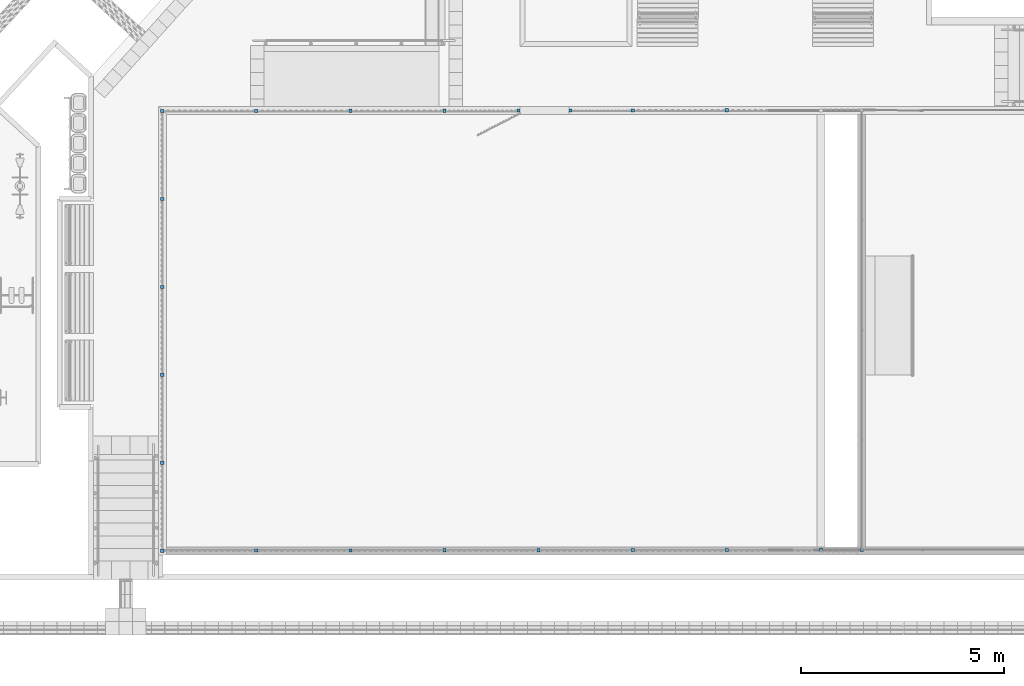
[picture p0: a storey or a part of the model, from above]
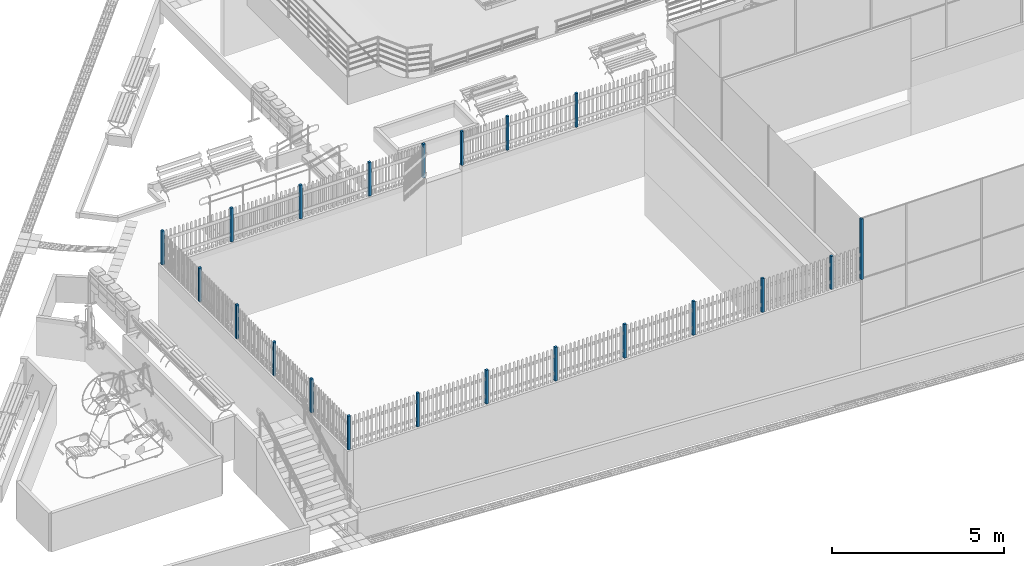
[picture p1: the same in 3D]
Properties of the parts of a building model (IFC2X3), part 1 of 2

# File
Description: ViewDefinition [CoordinationView_V2.0, QuantityTakeOffAddOnView], Option [Elements to export: Visible elements (on all stories)], Option [Partial Structure Display: Entire Model], Option [IFC Domain: All], Option [Structural Function: All Elements], Option [Convert Grid elements: On], Option [Convert IFC Annotations and ARCHICAD 2D elements: Off], Option [Convert 2D symbols of Doors and Windows: Off], Option [Export geometries that Participates in Collision Detection only: Off], Option [Split complex elements: Off], Option [Material Preservation: Explode where necessary], Option [Elements in Solid Element Operations: Extruded/revolved], Option [Elements with junctions: Extruded/revolved without junctions], Option [IFC Site Location: At Project Origin], Option [Curtain Wall export mode: Container Element], Option [Railing export mode: Single Element], Option [Stair export mode: Container Element], Option [Properties To Export: All properties], Option [Space containment: Off], Option [Bounding Box: Off], Option [Geometry to type objects: Off], Option [Element Properties: Visible Only], Option [Building Material Properties: Off], Option [Element Parameters: Off], Option [Component Parameters: All], Option [IFC Base Quantities: On], Option [Door Window Parameters: On], Option [IFC Space boundaries: Off], Option [ARCHICAD Zone Categories as IFC Space classification data: Off], Option [Element Classifications: On]
File name: C:\Users\Cleber\Desktop\Obra PRAÇA VILA SÃO JORGE. 22 SETEMBRO.ifc
Time: 2023-09-26T13:36:35
Author: Architect
Organization: Building Designer Office
Written by: The EXPRESS Data Manager Version 5.02.0100.09 : 26 Sep 2013
Made in: IFC file generated by GRAPHISOFT ARCHICAD 25.0.0 BRA FULL Windows version (IFC add-on version: 3002 BRA FULL).
Authorization: The authorising person

# IfcSite, Local
RefLatitude: -23, -32, 0, 0; RefLongitude: -46, -38, 0, 0; RefElevation: 0 mm
BaseQuantities - GrossPerimeter: 0 mm; GrossArea: 0 m2

# IfcBuilding, Construção
BaseQuantities - GrossFloorArea: 0 m2

# IfcBuildingStorey, Pavimento Térreo
In: Construção
Elevation: 0 mm
BaseQuantities - NetHeight: 3000 mm; GrossHeight: 3000 mm; Height: 3000 mm; GrossFloorArea: 0 m2

# IfcBeam: GENÉRICO - ESTRUTURAL 120 x 1000 (2)
In: Pavimento Térreo
Classification: Viga (Classificação ARCHICAD); Material: GENÉRICO - ESTRUTURAL
AC_Pset_RenovationAndPhasing - Renovation Status: Existing
Pset_BeamCommon - Reference: GENÉRICO - ESTRUTURAL 120 x 1000
Component Properties - Component 1, Tipo de Componente: Núcleo
BaseQuantities - Width: 120 mm; Depth: 999.792 mm; CrossSectionArea: 0.119975 m2
Component Quantities - Component 1, Espessura do Componente: 120 mm; Component 1, Altura do Componente Retangular: 999.792 mm; Component 1, Largura do Componente Retangular: 120 mm; Component 1, Área de Seção Transversal do Componente: 0.119975 m2
Name | Component 1, Carbono Incorporado | Component 1, Energia Incorporada (MJ) | NetSurfaceAreaExtrudedSides (m2) = OuterSurfaceArea (m2) | Length (mm) | TotalSurfaceArea (m2) = GrossSurfaceArea (m2) = NetSurfaceArea (m2) | GrossVolume (m3) | NetVolume (m3) = Component 1, Volume Componente (Líquido) (m3) = Component 1, Volume do componente (Bruto) (m3) | Component 1, Massa (kg) | Component 1, Área de Componente Projetada (Líquida) (m2) = Component 1, Área de Componente Projetada (Bruta) (m2)
Viga-032 | 41.9005 (kgCO₂) | 406.308 | 1.69798 | 1462.07 | 1.93793 | 0.174822 | 0.0920082 | 211.619 | 0.784363
Viga-032 | 79.3958 (kgCO₂) | 769.898 | 3.24369 | 1493.59 | 3.48364 | 0.177655 | 0.174343 | 400.989 | 1.4932

# IfcBeam: GENÉRICO - ESTRUTURAL 120 x 1362 (8)
In: Pavimento Térreo
Classification: Viga (Classificação ARCHICAD); Material: GENÉRICO - ESTRUTURAL
AC_Pset_RenovationAndPhasing - Renovation Status: Existing
Pset_BeamCommon - Reference: GENÉRICO - ESTRUTURAL 120 x 1362
Component Properties - Component 1, Tipo de Componente: Núcleo
BaseQuantities - Width: 120 mm; Depth: 1361.64 mm; CrossSectionArea: 0.163396 m2
Component Quantities - Component 1, Espessura do Componente: 120 mm; Component 1, Altura do Componente Retangular: 1361.64 mm; Component 1, Largura do Componente Retangular: 120 mm; Component 1, Área de Seção Transversal do Componente: 0.163396 m2
Name | Component 1, Carbono Incorporado | Component 1, Energia Incorporada (MJ) | NetSurfaceAreaExtrudedSides (m2) = OuterSurfaceArea (m2) | Length (mm) | TotalSurfaceArea (m2) = GrossSurfaceArea (m2) = NetSurfaceArea (m2) | GrossVolume (m3) | NetVolume (m3) = Component 1, Volume Componente (Líquido) (m3) = Component 1, Volume do componente (Bruto) (m3) | Component 1, Massa (kg) | Component 1, Área de Componente Projetada (Líquida) (m2) = Component 1, Área de Componente Projetada (Bruta) (m2)
Viga-031 | 380.983 (kgCO₂) | 3694.38 | 15.172 | 5240 | 15.4987 | 0.836589 | 0.836589 | 1924.16 | 7.10132
Viga-031 | 581.999 (kgCO₂) | 5643.63 | 23.1771 | 7907.69 | 23.5039 | 1.278 | 1.278 | 2939.39 | 10.7674
Viga-031 | 110.547 (kgCO₂) | 1071.97 | 4.40235 | 1511.88 | 4.72914 | 0.242748 | 0.242748 | 558.32 | 2.05863
Viga-031 | 118.178 (kgCO₂) | 1145.97 | 4.7643 | 1656.84 | 5.09109 | 0.266916 | 0.259503 | 596.857 | 2.25602
Viga-032 | 369.15 (kgCO₂) | 3579.64 | 14.7007 | 5007.56 | 15.0275 | 0.810606 | 0.810606 | 1864.39 | 6.81848
Viga-031 | 426.373 (kgCO₂) | 4134.53 | 16.9796 | 5850 | 17.3063 | 0.936261 | 0.936261 | 2153.4 | 7.96557
Viga-031 | 16.4181 (kgCO₂) | 159.206 | 0.653821 | 220.642 | 0.980614 | 0.036052 | 0.036052 | 82.9197 | 0.300434
Viga-031 | 138.486 (kgCO₂) | 1342.9 | 5.51497 | 1944.4 | 5.84176 | 0.304098 | 0.304098 | 699.426 | 2.64757

# IfcBeam: GENÉRICO - ESTRUTURAL 120 x 1535, Viga-030
In: Pavimento Térreo
Classification: Viga (Classificação ARCHICAD); Material: GENÉRICO - ESTRUTURAL
AC_Pset_RenovationAndPhasing - Renovation Status: Existing
Pset_BeamCommon - Reference: GENÉRICO - ESTRUTURAL 120 x 1535
Component Properties - Component 1, Carbono Incorporado: 63.7385 (kgCO₂); Component 1, Energia Incorporada: 618.07 MJ; Component 1, Tipo de Componente: Núcleo
BaseQuantities - NetSurfaceAreaExtrudedSides: 2.51505 m2; Length: 911.723 mm; Width: 120 mm; Depth: 1535.02 mm; CrossSectionArea: 0.184202 m2; OuterSurfaceArea: 2.51505 m2; TotalSurfaceArea: 2.88345 m2; GrossSurfaceArea: 2.88345 m2; GrossVolume: 0.139961 m3; NetSurfaceArea: 2.88345 m2; NetVolume: 0.139961 m3
Component Quantities - Component 1, Massa: 321.911 kg; Component 1, Área de Componente Projetada (Líquida): 1.368 m2; Component 1, Área de Componente Projetada (Bruta): 1.368 m2; Component 1, Espessura do Componente: 120 mm; Component 1, Altura do Componente Retangular: 1535.02 mm; Component 1, Largura do Componente Retangular: 120 mm; Component 1, Área de Seção Transversal do Componente: 0.184202 m2; Component 1, Volume Componente (Líquido): 0.139961 m3; Component 1, Volume do componente (Bruto): 0.139961 m3

# IfcBeam: GENÉRICO - ESTRUTURAL 120 x 2013, Viga-030
In: Pavimento Térreo
Classification: Viga (Classificação ARCHICAD); Material: GENÉRICO - ESTRUTURAL
AC_Pset_RenovationAndPhasing - Renovation Status: Existing
Pset_BeamCommon - Reference: GENÉRICO - ESTRUTURAL 120 x 2013
Component Properties - Component 1, Carbono Incorporado: 146.516 (kgCO₂); Component 1, Energia Incorporada: 1420.76 MJ; Component 1, Tipo de Componente: Núcleo
BaseQuantities - NetSurfaceAreaExtrudedSides: 5.68184 m2; Length: 1440.63 mm; Width: 120 mm; Depth: 2012.87 mm; CrossSectionArea: 0.241545 m2; OuterSurfaceArea: 5.68184 m2; TotalSurfaceArea: 6.16493 m2; GrossSurfaceArea: 6.16493 m2; GrossVolume: 0.32173 m3; NetSurfaceArea: 6.16493 m2; NetVolume: 0.32173 m3
Component Quantities - Component 1, Massa: 739.979 kg; Component 1, Área de Componente Projetada (Líquida): 2.80498 m2; Component 1, Área de Componente Projetada (Bruta): 2.80498 m2; Component 1, Espessura do Componente: 120 mm; Component 1, Altura do Componente Retangular: 2012.87 mm; Component 1, Largura do Componente Retangular: 120 mm; Component 1, Área de Seção Transversal do Componente: 0.241545 m2; Component 1, Volume Componente (Líquido): 0.32173 m3; Component 1, Volume do componente (Bruto): 0.32173 m3

# IfcBeam: GENÉRICO - ESTRUTURAL 120 x 340, Viga-032
In: Pavimento Térreo
Classification: Viga (Classificação ARCHICAD); Material: GENÉRICO - ESTRUTURAL
AC_Pset_RenovationAndPhasing - Renovation Status: Existing
Pset_BeamCommon - Reference: GENÉRICO - ESTRUTURAL 120 x 340
Component Properties - Component 1, Carbono Incorporado: 412.235 (kgCO₂); Component 1, Energia Incorporada: 3997.43 MJ; Component 1, Tipo de Componente: Núcleo
BaseQuantities - NetSurfaceAreaExtrudedSides: 20.4091 m2; Length: 22225.5 mm; Width: 120 mm; Depth: 340.166 mm; CrossSectionArea: 0.04082 m2; OuterSurfaceArea: 20.4091 m2; TotalSurfaceArea: 20.4908 m2; GrossSurfaceArea: 20.4908 m2; GrossVolume: 0.906422 m3; NetSurfaceArea: 20.4908 m2; NetVolume: 0.905215 m3
Component Quantities - Component 1, Massa: 2081.99 kg; Component 1, Área de Componente Projetada (Líquida): 7.56037 m2; Component 1, Área de Componente Projetada (Bruta): 7.56037 m2; Component 1, Espessura do Componente: 120 mm; Component 1, Altura do Componente Retangular: 340.166 mm; Component 1, Largura do Componente Retangular: 120 mm; Component 1, Área de Seção Transversal do Componente: 0.04082 m2; Component 1, Volume Componente (Líquido): 0.905215 m3; Component 1, Volume do componente (Bruto): 0.905215 m3

# IfcBeam: GENÉRICO - ESTRUTURAL 120 x 500 (2)
In: Pavimento Térreo
Classification: Viga (Classificação ARCHICAD); Material: GENÉRICO - ESTRUTURAL
AC_Pset_RenovationAndPhasing - Renovation Status: Existing
Pset_BeamCommon - Reference: GENÉRICO - ESTRUTURAL 120 x 500
Component Properties - Component 1, Tipo de Componente: Núcleo
BaseQuantities - Width: 120 mm; Depth: 499.897 mm; CrossSectionArea: 0.0599877 m2
Component Quantities - Component 1, Espessura do Componente: 120 mm; Component 1, Altura do Componente Retangular: 499.897 mm; Component 1, Largura do Componente Retangular: 120 mm; Component 1, Área de Seção Transversal do Componente: 0.0599877 m2
Name | Component 1, Carbono Incorporado | Component 1, Energia Incorporada (MJ) | NetSurfaceAreaExtrudedSides (m2) = OuterSurfaceArea (m2) | Length (mm) | TotalSurfaceArea (m2) = GrossSurfaceArea (m2) = NetSurfaceArea (m2) | GrossVolume (m3) | NetVolume (m3) = Component 1, Volume Componente (Líquido) (m3) = Component 1, Volume do componente (Bruto) (m3) | Component 1, Massa (kg) | Component 1, Área de Componente Projetada (Líquida) (m2) = Component 1, Área de Componente Projetada (Bruta) (m2)
Viga-032 | 193.354 (kgCO₂) | 1874.95 | 12.4029 | 22225.8 | 12.5229 | 1.33029 | 0.424581 | 976.537 | 3.54959
Viga-032 | 40.92 (kgCO₂) | 396.8 | 1.85708 | 1586.63 | 1.97706 | 0.089856 | 0.0898551 | 206.667 | 0.78175

# IfcBeam: GENÉRICO - ESTRUTURAL 120 x 580, Viga-030
In: Pavimento Térreo
Classification: Viga (Classificação ARCHICAD); Material: GENÉRICO - ESTRUTURAL
AC_Pset_RenovationAndPhasing - Renovation Status: Existing
Pset_BeamCommon - Reference: GENÉRICO - ESTRUTURAL 120 x 580
Component Properties - Component 1, Carbono Incorporado: 157.502 (kgCO₂); Component 1, Energia Incorporada: 1527.3 MJ; Component 1, Tipo de Componente: Núcleo
BaseQuantities - NetSurfaceAreaExtrudedSides: 6.92989 m2; Length: 4976.72 mm; Width: 120 mm; Depth: 579.51 mm; CrossSectionArea: 0.0695413 m2; OuterSurfaceArea: 6.92989 m2; TotalSurfaceArea: 7.06897 m2; GrossSurfaceArea: 7.06897 m2; GrossVolume: 0.345858 m3; NetSurfaceArea: 7.06897 m2; NetVolume: 0.345855 m3
Component Quantities - Component 1, Massa: 795.467 kg; Component 1, Área de Componente Projetada (Líquida): 2.88215 m2; Component 1, Área de Componente Projetada (Bruta): 2.88215 m2; Component 1, Espessura do Componente: 120 mm; Component 1, Altura do Componente Retangular: 579.51 mm; Component 1, Largura do Componente Retangular: 120 mm; Component 1, Área de Seção Transversal do Componente: 0.0695413 m2; Component 1, Volume Componente (Líquido): 0.345855 m3; Component 1, Volume do componente (Bruto): 0.345855 m3

# IfcBeam: GENÉRICO - ESTRUTURAL 120 x 585 (3)
In: Pavimento Térreo
Classification: Viga (Classificação ARCHICAD); Material: GENÉRICO - ESTRUTURAL
AC_Pset_RenovationAndPhasing - Renovation Status: Existing
Pset_BeamCommon - Reference: GENÉRICO - ESTRUTURAL 120 x 585
Component Properties - Component 1, Tipo de Componente: Núcleo
BaseQuantities - Width: 120 mm; Depth: 584.595 mm; CrossSectionArea: 0.0701514 m2
Component Quantities - Component 1, Espessura do Componente: 120 mm; Component 1, Altura do Componente Retangular: 584.595 mm; Component 1, Largura do Componente Retangular: 120 mm; Component 1, Área de Seção Transversal do Componente: 0.0701514 m2
Name | Component 1, Carbono Incorporado | Component 1, Energia Incorporada (MJ) | NetSurfaceAreaExtrudedSides (m2) = OuterSurfaceArea (m2) | Length (mm) | TotalSurfaceArea (m2) = GrossSurfaceArea (m2) = NetSurfaceArea (m2) | GrossVolume (m3) | NetVolume (m3) = Component 1, Volume Componente (Líquido) (m3) = Component 1, Volume do componente (Bruto) (m3) | Component 1, Massa (kg) | Component 1, Área de Componente Projetada (Líquida) (m2) = Component 1, Área de Componente Projetada (Bruta) (m2)
Viga-031 | 326.185 (kgCO₂) | 3163.01 | 14.388 | 10254.9 | 14.5283 | 0.716272 | 0.716261 | 1647.4 | 5.96893
Viga-031 | 37.8124 (kgCO₂) | 366.666 | 1.67025 | 1231.48 | 1.81055 | 0.0832676 | 0.0830312 | 190.972 | 0.693897
Viga-031 | 41.8068 (kgCO₂) | 405.399 | 1.84411 | 1322.81 | 1.98441 | 0.0918023 | 0.0918023 | 211.145 | 0.765019

# IfcBeam: GENÉRICO - ESTRUTURAL 120 x 725, Viga-032
In: Pavimento Térreo
Classification: Viga (Classificação ARCHICAD); Material: GENÉRICO - ESTRUTURAL
AC_Pset_RenovationAndPhasing - Renovation Status: Existing
Pset_BeamCommon - Reference: GENÉRICO - ESTRUTURAL 120 x 725
Component Properties - Component 1, Carbono Incorporado: 5.61509 (kgCO₂); Component 1, Energia Incorporada: 54.4493 MJ; Component 1, Tipo de Componente: Núcleo
BaseQuantities - NetSurfaceAreaExtrudedSides: 0.382527 m2; Length: 1494.2 mm; Width: 120 mm; Depth: 724.825 mm; CrossSectionArea: 0.086979 m2; OuterSurfaceArea: 0.382527 m2; TotalSurfaceArea: 0.556485 m2; GrossSurfaceArea: 0.556485 m2; GrossVolume: 0.125256 m3; NetSurfaceArea: 0.556485 m2; NetVolume: 0.01233 m3
Component Quantities - Component 1, Massa: 28.359 kg; Component 1, Área de Componente Projetada (Líquida): 0.111382 m2; Component 1, Área de Componente Projetada (Bruta): 0.111382 m2; Component 1, Espessura do Componente: 120 mm; Component 1, Altura do Componente Retangular: 724.825 mm; Component 1, Largura do Componente Retangular: 120 mm; Component 1, Área de Seção Transversal do Componente: 0.086979 m2; Component 1, Volume Componente (Líquido): 0.01233 m3; Component 1, Volume do componente (Bruto): 0.01233 m3

# IfcBeam: GENÉRICO - ESTRUTURAL 120 x 766, Viga-031
In: Pavimento Térreo
Classification: Viga (Classificação ARCHICAD); Material: GENÉRICO - ESTRUTURAL
AC_Pset_RenovationAndPhasing - Renovation Status: Existing
Pset_BeamCommon - Reference: GENÉRICO - ESTRUTURAL 120 x 766
Component Properties - Component 1, Carbono Incorporado: 50.8274 (kgCO₂); Component 1, Energia Incorporada: 492.872 MJ; Component 1, Tipo de Componente: Núcleo
BaseQuantities - NetSurfaceAreaExtrudedSides: 2.1515 m2; Length: 1295.36 mm; Width: 120 mm; Depth: 766.231 mm; CrossSectionArea: 0.0919477 m2; OuterSurfaceArea: 2.1515 m2; TotalSurfaceArea: 2.33539 m2; GrossSurfaceArea: 2.33539 m2; GrossVolume: 0.111611 m3; NetSurfaceArea: 2.33539 m2; NetVolume: 0.11161 m3
Component Quantities - Component 1, Massa: 256.704 kg; Component 1, Área de Componente Projetada (Líquida): 0.930088 m2; Component 1, Área de Componente Projetada (Bruta): 0.930088 m2; Component 1, Espessura do Componente: 120 mm; Component 1, Altura do Componente Retangular: 766.231 mm; Component 1, Largura do Componente Retangular: 120 mm; Component 1, Área de Seção Transversal do Componente: 0.0919477 m2; Component 1, Volume Componente (Líquido): 0.111611 m3; Component 1, Volume do componente (Bruto): 0.111611 m3

# IfcBeam: GENÉRICO - ESTRUTURAL 120 x 826, Viga-032
In: Pavimento Térreo
Classification: Viga (Classificação ARCHICAD); Material: GENÉRICO - ESTRUTURAL
AC_Pset_RenovationAndPhasing - Renovation Status: Existing
Pset_BeamCommon - Reference: GENÉRICO - ESTRUTURAL 120 x 826
Component Properties - Component 1, Carbono Incorporado: 34.3697 (kgCO₂); Component 1, Energia Incorporada: 333.282 MJ; Component 1, Tipo de Componente: Núcleo
BaseQuantities - NetSurfaceAreaExtrudedSides: 1.4405 m2; Length: 910.737 mm; Width: 120 mm; Depth: 826.435 mm; CrossSectionArea: 0.0991722 m2; OuterSurfaceArea: 1.4405 m2; TotalSurfaceArea: 1.63885 m2; GrossSurfaceArea: 1.63885 m2; GrossVolume: 0.0754715 m3; NetSurfaceArea: 1.63885 m2; NetVolume: 0.0754715 m3
Component Quantities - Component 1, Massa: 173.584 kg; Component 1, Área de Componente Projetada (Líquida): 0.752142 m2; Component 1, Área de Componente Projetada (Bruta): 0.752142 m2; Component 1, Espessura do Componente: 120 mm; Component 1, Altura do Componente Retangular: 826.435 mm; Component 1, Largura do Componente Retangular: 120 mm; Component 1, Área de Seção Transversal do Componente: 0.0991722 m2; Component 1, Volume Componente (Líquido): 0.0754715 m3; Component 1, Volume do componente (Bruto): 0.0754715 m3

# IfcBeam: GENÉRICO - ESTRUTURAL 120 x 835, Viga-033
In: Pavimento Térreo
Classification: Viga (Classificação ARCHICAD); Material: GENÉRICO - ESTRUTURAL
AC_Pset_RenovationAndPhasing - Renovation Status: Existing
Pset_BeamCommon - Reference: GENÉRICO - ESTRUTURAL 120 x 835
Component Properties - Component 1, Carbono Incorporado: 137.254 (kgCO₂); Component 1, Energia Incorporada: 1330.95 MJ; Component 1, Tipo de Componente: Núcleo
BaseQuantities - NetSurfaceAreaExtrudedSides: 5.74554 m2; Length: 3101.42 mm; Width: 120 mm; Depth: 834.502 mm; CrossSectionArea: 0.10014 m2; OuterSurfaceArea: 5.74554 m2; TotalSurfaceArea: 5.94582 m2; GrossSurfaceArea: 5.94582 m2; GrossVolume: 0.301393 m3; NetSurfaceArea: 5.94582 m2; NetVolume: 0.301393 m3
Component Quantities - Component 1, Massa: 693.203 kg; Component 1, Área de Componente Projetada (Líquida): 2.56793 m2; Component 1, Área de Componente Projetada (Bruta): 2.56793 m2; Component 1, Espessura do Componente: 120 mm; Component 1, Altura do Componente Retangular: 834.502 mm; Component 1, Largura do Componente Retangular: 120 mm; Component 1, Área de Seção Transversal do Componente: 0.10014 m2; Component 1, Volume Componente (Líquido): 0.301393 m3; Component 1, Volume do componente (Bruto): 0.301393 m3

# IfcBeam: GENÉRICO - ESTRUTURAL 120 x 919 (18)
In: Pavimento Térreo
Classification: Viga (Classificação ARCHICAD); Material: GENÉRICO - ESTRUTURAL
AC_Pset_RenovationAndPhasing - Renovation Status: Existing
Pset_BeamCommon - Reference: GENÉRICO - ESTRUTURAL 120 x 919
Component Properties - Component 1, Tipo de Componente: Núcleo
BaseQuantities - Width: 120 mm; Depth: 919.288 mm; CrossSectionArea: 0.110315 m2
Component Quantities - Component 1, Espessura do Componente: 120 mm; Component 1, Altura do Componente Retangular: 919.288 mm; Component 1, Largura do Componente Retangular: 120 mm; Component 1, Área de Seção Transversal do Componente: 0.110315 m2
Name | Component 1, Carbono Incorporado | Component 1, Energia Incorporada (MJ) | NetSurfaceAreaExtrudedSides (m2) = OuterSurfaceArea (m2) | Length (mm) | TotalSurfaceArea (m2) = GrossSurfaceArea (m2) = NetSurfaceArea (m2) | GrossVolume (m3) | NetVolume (m3) = Component 1, Volume Componente (Líquido) (m3) = Component 1, Volume do componente (Bruto) (m3) | Component 1, Massa (kg) | Component 1, Área de Componente Projetada (Líquida) (m2) = Component 1, Área de Componente Projetada (Bruta) (m2)
Viga-030 | 106.903 (kgCO₂) | 1036.63 | 4.42318 | 2164.82 | 4.64381 | 0.234748 | 0.234745 | 539.913 | 1.95624
Viga-030 | 24.6152 (kgCO₂) | 238.693 | 1.02325 | 544.505 | 1.24388 | 0.0595885 | 0.0540518 | 124.319 | 0.45064
Viga-030 | 37.6315 (kgCO₂) | 364.911 | 1.55701 | 756.572 | 1.77764 | 0.0826339 | 0.0826339 | 190.058 | 0.688616
Viga-031 | 1133.76 (kgCO₂) | 10994 | 46.9173 | 22648.5 | 47.1379 | 2.49982 | 2.48959 | 5726.06 | 20.7466
Viga-032 | 650.457 (kgCO₂) | 6307.46 | 26.9128 | 12972.3 | 27.1334 | 1.42832 | 1.42832 | 3285.14 | 11.9027
Viga-030 | 656.273 (kgCO₂) | 6363.86 | 27.1534 | 13314.7 | 27.3741 | 1.44109 | 1.44109 | 3314.51 | 12.1371
Viga-030 | 58.5463 (kgCO₂) | 567.722 | 2.42244 | 1270.82 | 2.64307 | 0.128564 | 0.12856 | 295.688 | 1.10597
Viga-031 | 414.104 (kgCO₂) | 4015.56 | 17.1333 | 8304.88 | 17.3539 | 0.909343 | 0.90932 | 2091.44 | 7.59058
Viga-031 | 2067.89 (kgCO₂) | 20052.3 | 85.5594 | 41211.6 | 85.78 | 4.54082 | 4.54082 | 10443.9 | 37.8402
Viga-031 | 38.621 (kgCO₂) | 374.507 | 1.59795 | 768.772 | 1.81858 | 0.0848067 | 0.0848067 | 195.055 | 0.706723
Viga-030 | 36.961 (kgCO₂) | 358.41 | 1.52927 | 760.809 | 1.7499 | 0.0811617 | 0.0811617 | 186.672 | 0.676348
Viga-030 | 4.45229 (kgCO₂) | 43.1737 | 0.190464 | 214.343 | 0.411093 | 0.0167333 | 0.00977666 | 22.4863 | 0.109912
Viga-030 | 158.607 (kgCO₂) | 1538.01 | 6.5624 | 3225.61 | 6.78303 | 0.348286 | 0.348282 | 801.047 | 2.92697
Viga-030 | 363.83 (kgCO₂) | 3528.05 | 15.0535 | 7481.73 | 15.2742 | 0.798924 | 0.798924 | 1837.52 | 6.77924
Viga-032 | 192.432 (kgCO₂) | 1866.01 | 10.9101 | 6921.34 | 11.1308 | 0.756157 | 0.422556 | 971.879 | 6.31226
Viga-032 | 236.974 (kgCO₂) | 2297.93 | 9.81061 | 4767.43 | 10.0312 | 0.520365 | 0.520365 | 1196.84 | 4.3393
Viga-031 | 1234.43 (kgCO₂) | 11970.2 | 51.0293 | 24643.2 | 51.25 | 2.71066 | 2.71065 | 6234.49 | 22.5889
Viga-030 | 67.0916 (kgCO₂) | 650.585 | 2.77589 | 1372.31 | 2.99652 | 0.160571 | 0.147325 | 338.847 | 1.22769

# IfcBeam: GENÉRICO - ESTRUTURAL 150 x 300 (3)
In: Pavimento Térreo
Classification: Viga (Classificação ARCHICAD); Material: GENÉRICO - ESTRUTURAL
AC_Pset_RenovationAndPhasing - Renovation Status: Existing
Pset_BeamCommon - Reference: GENÉRICO - ESTRUTURAL 150 x 300
Component Properties - Component 1, Tipo de Componente: Núcleo
BaseQuantities - Width: 150 mm; Depth: 300 mm; CrossSectionArea: 0.045 m2
Component Quantities - Component 1, Espessura do Componente: 150 mm; Component 1, Altura do Componente Retangular: 300 mm; Component 1, Largura do Componente Retangular: 150 mm; Component 1, Área de Seção Transversal do Componente: 0.045 m2
Name | Component 1, Carbono Incorporado | Component 1, Energia Incorporada (MJ) | NetSurfaceAreaExtrudedSides (m2) = OuterSurfaceArea (m2) | Length (mm) | TotalSurfaceArea (m2) = GrossSurfaceArea (m2) = NetSurfaceArea (m2) | GrossVolume (m3) = NetVolume (m3) = Component 1, Volume Componente (Líquido) (m3) = Component 1, Volume do componente (Bruto) (m3) | Component 1, Massa (kg) | Component 1, Área de Componente Projetada (Líquida) (m2) = Component 1, Área de Componente Projetada (Bruta) (m2)
Viga-032 | 30.7395 (kgCO₂) | 298.08 | 1.35 | 1500 | 1.44 | 0.0675 | 155.25 | 0.45
Viga-032 | 40.9602 (kgCO₂) | 397.19 | 1.79887 | 1998.74 | 1.88887 | 0.0899434 | 206.87 | 0.599623
Viga-032 | 88.2772 (kgCO₂) | 856.021 | 3.87691 | 4325.61 | 3.96691 | 0.193845 | 445.844 | 1.2923

# IfcBeam: GENÉRICO - ESTRUTURAL 200 x 1997, Viga-032
In: Pavimento Térreo
Classification: Viga (Classificação ARCHICAD); Material: GENÉRICO - ESTRUTURAL
AC_Pset_RenovationAndPhasing - Renovation Status: Existing
Pset_BeamCommon - Reference: GENÉRICO - ESTRUTURAL 200 x 1997
Component Properties - Component 1, Carbono Incorporado: 3058.17 (kgCO₂); Component 1, Energia Incorporada: 29655 MJ; Component 1, Tipo de Componente: Núcleo
BaseQuantities - NetSurfaceAreaExtrudedSides: 73.8784 m2; Length: 16929.8 mm; Width: 200 mm; Depth: 1997.15 mm; CrossSectionArea: 0.399429 m2; OuterSurfaceArea: 73.8784 m2; TotalSurfaceArea: 74.6773 m2; GrossSurfaceArea: 74.6773 m2; GrossVolume: 6.71536 m3; NetSurfaceArea: 74.6773 m2; NetVolume: 6.71535 m3
Component Quantities - Component 1, Massa: 15445.3 kg; Component 1, Área de Componente Projetada (Líquida): 33.5768 m2; Component 1, Área de Componente Projetada (Bruta): 33.5768 m2; Component 1, Espessura do Componente: 200 mm; Component 1, Altura do Componente Retangular: 1997.15 mm; Component 1, Largura do Componente Retangular: 200 mm; Component 1, Área de Seção Transversal do Componente: 0.399429 m2; Component 1, Volume Componente (Líquido): 6.71535 m3; Component 1, Volume do componente (Bruto): 6.71535 m3

# IfcBeam: GENÉRICO - ESTRUTURAL 400 x 20 (24)
In: Pavimento Térreo
Classification: Viga (Classificação ARCHICAD); Material: GENÉRICO - ESTRUTURAL
AC_Pset_RenovationAndPhasing - Renovation Status: Existing
Pset_BeamCommon - Reference: GENÉRICO - ESTRUTURAL 400 x 20
Component Properties - Component 1, Tipo de Componente: Núcleo
BaseQuantities - Width: 400 mm; Depth: 20 mm; CrossSectionArea: 0.008 m2
Component Quantities - Component 1, Espessura do Componente: 400 mm; Component 1, Altura do Componente Retangular: 20 mm; Component 1, Largura do Componente Retangular: 400 mm; Component 1, Área de Seção Transversal do Componente: 0.008 m2
Name | Component 1, Carbono Incorporado | Component 1, Energia Incorporada (MJ) | NetSurfaceAreaExtrudedSides (m2) = OuterSurfaceArea (m2) | Length (mm) | TotalSurfaceArea (m2) = GrossSurfaceArea (m2) = NetSurfaceArea (m2) | GrossVolume (m3) = NetVolume (m3) = Component 1, Volume Componente (Líquido) (m3) = Component 1, Volume do componente (Bruto) (m3) | Component 1, Massa (kg) | Component 1, Área de Componente Projetada (Líquida) (m2) = Component 1, Área de Componente Projetada (Bruta) (m2)
7 x Viga-031 | 14.5899 (kgCO₂) | 141.478 | 3.36394 | 4005.66 | 3.37994 | 0.0320375 | 73.6863 | 0.0800938
2 x Viga-031 | 14.6156 (kgCO₂) | 141.727 | 3.36988 | 4013.29 | 3.38588 | 0.0320941 | 73.8164 | 0.0802352
2 x Viga-031 | 14.6207 (kgCO₂) | 141.776 | 3.37104 | 4014.77 | 3.38704 | 0.0321052 | 73.8419 | 0.0802629
6 x Viga-031 | 14.6214 (kgCO₂) | 141.784 | 3.37121 | 4014.98 | 3.38721 | 0.0321068 | 73.8456 | 0.080267
2 x Viga-031 | 14.6188 (kgCO₂) | 141.758 | 3.37061 | 4014.22 | 3.38661 | 0.032101 | 73.8324 | 0.0802526
2 x Viga-031 | 14.6184 (kgCO₂) | 141.754 | 3.37051 | 4014.09 | 3.38651 | 0.0321001 | 73.8301 | 0.0802502
2 x Viga-031 | 14.6167 (kgCO₂) | 141.737 | 3.37011 | 4013.59 | 3.38611 | 0.0320963 | 73.8215 | 0.0802407
Viga-031 | 14.5896 (kgCO₂) | 141.475 | 3.36388 | 4005.59 | 3.37988 | 0.032037 | 73.6851 | 0.0800925

# IfcBeam: GENÉRICO - ESTRUTURAL D30 (18)
In: Pavimento Térreo
Classification: Viga (Classificação ARCHICAD); Material: GENÉRICO - ESTRUTURAL
AC_Pset_RenovationAndPhasing - Renovation Status: Existing
Pset_BeamCommon - Reference: GENÉRICO - ESTRUTURAL D30
Component Properties - Component 1, Tipo de Componente: Núcleo
BaseQuantities - Width: 30 mm; Depth: 30 mm; CrossSectionArea: 0.000706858 m2
Component Quantities - Component 1, Espessura do Componente: 30 mm; Component 1, Área de Seção Transversal do Componente: 0.000706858 m2
Name | Component 1, Carbono Incorporado | Component 1, Energia Incorporada (MJ) | NetSurfaceAreaExtrudedSides (m2) = OuterSurfaceArea (m2) | Length (mm) | TotalSurfaceArea (m2) = GrossSurfaceArea (m2) = NetSurfaceArea (m2) | GrossVolume (m3) | NetVolume (m3) = Component 1, Volume Componente (Líquido) (m3) = Component 1, Volume do componente (Bruto) (m3) | Component 1, Massa (kg) | Component 1, Área de Componente Projetada (Líquida) (m2) = Component 1, Área de Componente Projetada (Bruta) (m2)
Viga-027 | 5.89561 (kgCO₂) | 57.1695 | 1.78703 | 19194.3 | 1.78844 | 0.012946 | 0.012946 | 29.7758 | 0.575717
Viga-027 | 4.04221 (kgCO₂) | 39.1972 | 1.22524 | 13149.9 | 1.22665 | 0.00887617 | 0.00887617 | 20.4152 | 0.394496
2 x Viga-027 | 5.89819 (kgCO₂) | 57.1946 | 1.78781 | 19202.7 | 1.78922 | 0.0129517 | 0.0129517 | 29.7889 | 0.575968
2 x Viga-027 | 0.378806 (kgCO₂) | 3.67327 | 0.11482 | 1232.31 | 0.116234 | 0.000831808 | 0.000831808 | 1.91316 | 0.0369693
Viga-027 | 2.58116 (kgCO₂) | 25.0295 | 0.78238 | 8411.9 | 0.783793 | 0.00566791 | 0.00566791 | 13.0362 | 0.252244
2 x Viga-027 | 3.32376 (kgCO₂) | 32.2304 | 1.00747 | 10842.7 | 1.00888 | 0.00729854 | 0.00729854 | 16.7866 | 0.325055
Viga-027 | 5.65687 (kgCO₂) | 54.8545 | 1.71466 | 18417.4 | 1.71607 | 0.0124218 | 0.0124218 | 28.5701 | 0.552413
Viga-027 | 5.65651 (kgCO₂) | 54.851 | 1.71455 | 18431.5 | 1.71597 | 0.012421 | 0.012421 | 28.5683 | 0.552719
Viga-027 | 5.86844 (kgCO₂) | 56.9061 | 1.77879 | 19090.9 | 1.7802 | 0.0129517 | 0.0128863 | 29.6386 | 0.572727
2 x Viga-027 | 0.398666 (kgCO₂) | 3.86585 | 0.12084 | 1296.92 | 0.122254 | 0.000875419 | 0.000875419 | 2.01346 | 0.0389075
Viga-027 | 0.42468 (kgCO₂) | 4.11811 | 0.128725 | 1381.54 | 0.130139 | 0.000932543 | 0.000932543 | 2.14485 | 0.0414463
Viga-027 | 1.85759 (kgCO₂) | 18.013 | 0.563056 | 6058.01 | 0.564469 | 0.00407903 | 0.00407903 | 9.38176 | 0.181628
Viga-027 | 2.52535 (kgCO₂) | 24.4883 | 0.765463 | 8245.17 | 0.766877 | 0.00554535 | 0.00554535 | 12.7543 | 0.247132
Viga-027 | 0.456304 (kgCO₂) | 4.42476 | 0.138311 | 1484.42 | 0.139724 | 0.00100198 | 0.00100198 | 2.30456 | 0.0445327

# IfcBuildingElementPart (669)
In: Pavimento Térreo
Name | Material | Carbono Incorporado | Energia Incorporada (MJ) | Massa (kg) | Volume Componente (Líquido) (m3) = Volume do componente (Bruto) (m3)
60 x Aço - Inoxidável | Aço - Inoxidável | 55.581 (kgCO₂) | 512.429 | 9.03755 | 0.00114399
166 x Alumínio | Alumínio | 0.641337 (kgCO₂) | 10.8523 | 0.0700149 | 0.0000250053
Aço - Inoxidável | Aço - Inoxidável | 44.8041 (kgCO₂) | 413.072 | 7.28522 | 0.00092218
Aço - Inoxidável | Aço - Inoxidável | 45.3992 (kgCO₂) | 418.559 | 7.38199 | 0.000934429
2 x Aço - Inoxidável | Aço - Inoxidável | 65.4595 (kgCO₂) | 603.505 | 10.6438 | 0.00134732
16 x Aço - Inoxidável | Aço - Inoxidável | 23.994 (kgCO₂) | 221.213 | 3.90146 | 0.000493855
16 x Aço - Inoxidável | Aço - Inoxidável | 3.03721 (kgCO₂) | 28.0016 | 0.493855 | 0.0000625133
4 x Aço - Inoxidável | Aço - Inoxidável | 210.782 (kgCO₂) | 1943.31 | 34.2736 | 0.00433843
8 x Aço - Inoxidável | Aço - Inoxidável | 52.6956 (kgCO₂) | 485.828 | 8.56839 | 0.00108461
86 x Aço - Inoxidável | Aço - Inoxidável | 62.2628 (kgCO₂) | 574.033 | 10.124 | 0.00128152
16 x Aço - Inoxidável | Aço - Inoxidável | 1.21488 (kgCO₂) | 11.2006 | 0.197542 | 0.0000250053
Aço - Inoxidável | Aço - Inoxidável | 43.7977 (kgCO₂) | 403.794 | 7.12158 | 0.000901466
2 x Aço - Inoxidável | Aço - Inoxidável | 268.725 (kgCO₂) | 2477.51 | 43.6951 | 0.00553102
Aço - Inoxidável | Aço - Inoxidável | 271.951 (kgCO₂) | 2507.26 | 44.2197 | 0.00559744
5 x Aço - Inoxidável | Aço - Inoxidável | 67.9879 (kgCO₂) | 626.815 | 11.0549 | 0.00139936
2 x Aço - Inoxidável | Aço - Inoxidável | 509.678 (kgCO₂) | 4698.98 | 82.8745 | 0.0104904
Aço - Inoxidável | Aço - Inoxidável | 516.613 (kgCO₂) | 4762.92 | 84.0021 | 0.0106332
5 x Aço - Inoxidável | Aço - Inoxidável | 129.153 (kgCO₂) | 1190.73 | 21.0005 | 0.00265829
2 x Aço - Inoxidável | Aço - Inoxidável | 870.809 (kgCO₂) | 8028.44 | 141.595 | 0.0179234
Aço - Inoxidável | Aço - Inoxidável | 870.859 (kgCO₂) | 8028.9 | 141.603 | 0.0179244
5 x Aço - Inoxidável | Aço - Inoxidável | 217.715 (kgCO₂) | 2007.22 | 35.4008 | 0.00448111
Aço - Inoxidável | Aço - Inoxidável | 62.2629 (kgCO₂) | 574.033 | 10.124 | 0.00128152
Aço - Inoxidável | Aço - Inoxidável | 49.3079 (kgCO₂) | 454.595 | 8.01755 | 0.00101488
5 x Aço - Inoxidável | Aço - Inoxidável | 12.2593 (kgCO₂) | 113.025 | 1.99338 | 0.000252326
Aço - Inoxidável | Aço - Inoxidável | 73.8367 (kgCO₂) | 680.738 | 12.006 | 0.00151974
5 x Aço - Inoxidável | Aço - Inoxidável | 18.4932 (kgCO₂) | 170.499 | 3.00703 | 0.000380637
Aço - Inoxidável | Aço - Inoxidável | 60.837 (kgCO₂) | 560.887 | 9.89219 | 0.00125218
10 x Aço - Inoxidável | Aço - Inoxidável | 15.311 (kgCO₂) | 141.16 | 2.4896 | 0.000315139
Aço - Inoxidável | Aço - Inoxidável | 350.494 (kgCO₂) | 3231.38 | 56.9908 | 0.00721403
5 x Aço - Inoxidável | Aço - Inoxidável | 87.6234 (kgCO₂) | 807.845 | 14.2477 | 0.00180351
Aço - Inoxidável | Aço - Inoxidável | 60.8311 (kgCO₂) | 560.833 | 9.89123 | 0.00125205
5 x Aço - Inoxidável | Aço - Inoxidável | 15.3095 (kgCO₂) | 141.146 | 2.48934 | 0.000315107
Aço - Inoxidável | Aço - Inoxidável | 73.8343 (kgCO₂) | 680.716 | 12.0056 | 0.00151969
5 x Aço - Inoxidável | Aço - Inoxidável | 18.4927 (kgCO₂) | 170.493 | 3.00694 | 0.000380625
Aço - Inoxidável | Aço - Inoxidável | 49.2966 (kgCO₂) | 454.49 | 8.0157 | 0.00101465
5 x Aço - Inoxidável | Aço - Inoxidável | 12.2565 (kgCO₂) | 112.999 | 1.99293 | 0.00025227
3 x Aço - Inoxidável | Aço - Inoxidável | 45.1017 (kgCO₂) | 415.816 | 7.33361 | 0.000928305
Aço - Inoxidável | Aço - Inoxidável | 44.7969 (kgCO₂) | 413.006 | 7.28406 | 0.000922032
2 x Aço - Inoxidável | Aço - Inoxidável | 204.238 (kgCO₂) | 1882.97 | 33.2094 | 0.00420372
2 x Aço - Inoxidável | Aço - Inoxidável | 63.6916 (kgCO₂) | 587.206 | 10.3564 | 0.00131093
Aço - Inoxidável | Aço - Inoxidável | 45.7332 (kgCO₂) | 421.638 | 7.4363 | 0.000941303
Aço - Inoxidável | Aço - Inoxidável | 44.4702 (kgCO₂) | 409.993 | 7.23092 | 0.000915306
2 x Aço - Inoxidável | Aço - Inoxidável | 185.645 (kgCO₂) | 1711.56 | 30.1862 | 0.00382104
Aço - Inoxidável | Aço - Inoxidável | 44.4589 (kgCO₂) | 409.889 | 7.22909 | 0.000915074
Aço - Inoxidável | Aço - Inoxidável | 45.7445 (kgCO₂) | 421.742 | 7.43813 | 0.000941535
2 x Aço - Inoxidável | Aço - Inoxidável | 182.523 (kgCO₂) | 1682.77 | 29.6785 | 0.00375678
Aço - Inoxidável | Aço - Inoxidável | 62.2632 (kgCO₂) | 574.037 | 10.1241 | 0.00128153
Aço - Inoxidável | Aço - Inoxidável | 49.2684 (kgCO₂) | 454.23 | 8.01112 | 0.00101407
5 x Aço - Inoxidável | Aço - Inoxidável | 12.2489 (kgCO₂) | 112.929 | 1.99168 | 0.000252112
Aço - Inoxidável | Aço - Inoxidável | 73.854 (kgCO₂) | 680.898 | 12.0088 | 0.0015201
5 x Aço - Inoxidável | Aço - Inoxidável | 18.497 (kgCO₂) | 170.534 | 3.00765 | 0.000380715
Aço - Inoxidável | Aço - Inoxidável | 60.8337 (kgCO₂) | 560.857 | 9.89166 | 0.00125211
5 x Aço - Inoxidável | Aço - Inoxidável | 15.3102 (kgCO₂) | 141.152 | 2.48946 | 0.000315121
Aço - Inoxidável | Aço - Inoxidável | 350.492 (kgCO₂) | 3231.37 | 56.9906 | 0.007214
5 x Aço - Inoxidável | Aço - Inoxidável | 87.6231 (kgCO₂) | 807.842 | 14.2477 | 0.0018035
Aço - Inoxidável | Aço - Inoxidável | 60.837 (kgCO₂) | 560.888 | 9.8922 | 0.00125218
Aço - Inoxidável | Aço - Inoxidável | 73.8487 (kgCO₂) | 680.849 | 12.0079 | 0.00151999
5 x Aço - Inoxidável | Aço - Inoxidável | 18.4957 (kgCO₂) | 170.521 | 3.00743 | 0.000380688
Aço - Inoxidável | Aço - Inoxidável | 49.263 (kgCO₂) | 454.181 | 8.01024 | 0.00101395
5 x Aço - Inoxidável | Aço - Inoxidável | 12.2475 (kgCO₂) | 112.916 | 1.99147 | 0.000252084
2 x Aço - Inoxidável | Aço - Inoxidável | 84.5353 (kgCO₂) | 779.375 | 13.7456 | 0.00173995
Aço - Inoxidável | Aço - Inoxidável | 84.1181 (kgCO₂) | 775.528 | 13.6777 | 0.00173136
5 x Aço - Inoxidável | Aço - Inoxidável | 20.9314 (kgCO₂) | 192.978 | 3.40349 | 0.000430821
2 x Aço - Inoxidável | Aço - Inoxidável | 113.908 (kgCO₂) | 1050.17 | 18.5216 | 0.00234451
Aço - Inoxidável | Aço - Inoxidável | 117.954 (kgCO₂) | 1087.48 | 19.1796 | 0.00242779
5 x Aço - Inoxidável | Aço - Inoxidável | 29.3905 (kgCO₂) | 270.966 | 4.77895 | 0.00060493
2 x Aço - Inoxidável | Aço - Inoxidável | 109.406 (kgCO₂) | 1008.67 | 17.7895 | 0.00225184
Aço - Inoxidável | Aço - Inoxidável | 113.859 (kgCO₂) | 1049.72 | 18.5136 | 0.0023435
5 x Aço - Inoxidável | Aço - Inoxidável | 28.5427 (kgCO₂) | 263.15 | 4.64109 | 0.00058748
2 x Aço - Inoxidável | Aço - Inoxidável | 63.2661 (kgCO₂) | 583.282 | 10.2872 | 0.00130217
Aço - Inoxidável | Aço - Inoxidável | 62.4367 (kgCO₂) | 575.636 | 10.1523 | 0.0012851
5 x Aço - Inoxidável | Aço - Inoxidável | 15.6872 (kgCO₂) | 144.628 | 2.55077 | 0.000322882
2 x Aço - Inoxidável | Aço - Inoxidável | 45.0007 (kgCO₂) | 414.884 | 7.31718 | 0.000926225
2 x Aço - Inoxidável | Aço - Inoxidável | 45.2027 (kgCO₂) | 416.747 | 7.35003 | 0.000930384
4 x Aço - Inoxidável | Aço - Inoxidável | 196.686 (kgCO₂) | 1813.34 | 31.9814 | 0.00404828
2 x Aço - Estrutural | Aço - Estrutural | 25.6868 (kgCO₂) | 388.397 | 15.474 | 0.00198385
2 x Alumínio | Alumínio | 0.410368 (kgCO₂) | 6.944 | 0.0448 | 0.000016
2 x Aço - Inoxidável | Aço - Inoxidável | 316.015 (kgCO₂) | 2913.51 | 51.3846 | 0.00650438
Aço - Inoxidável | Aço - Inoxidável | 296.128 (kgCO₂) | 2730.16 | 48.1509 | 0.00609505
2 x Aço - Estrutural | Aço - Estrutural | 25.6894 (kgCO₂) | 388.435 | 15.4755 | 0.00198404
2 x Alumínio | Alumínio | 0.320668 (kgCO₂) | 5.42616 | 0.0350075 | 0.0000125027
Aço - Inoxidável | Aço - Inoxidável | 45.7972 (kgCO₂) | 422.227 | 7.44669 | 0.000942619
Aço - Inoxidável | Aço - Inoxidável | 44.4062 (kgCO₂) | 409.404 | 7.22052 | 0.00091399
2 x Aço - Inoxidável | Aço - Inoxidável | 242.128 (kgCO₂) | 2232.3 | 39.3704 | 0.00498359
Aço - Inoxidável | Aço - Inoxidável | 60.754 (kgCO₂) | 560.123 | 9.87871 | 0.00125047
2 x Aço - Inoxidável | Aço - Inoxidável | 9.09671 (kgCO₂) | 83.8672 | 1.47914 | 0.000187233
5 x Aço - Inoxidável | Aço - Inoxidável | 0.754395 (kgCO₂) | 6.95516 | 0.122666 | 0.0000155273
Aço - Inoxidável | Aço - Inoxidável | 3.06155 (kgCO₂) | 28.226 | 0.497813 | 0.0000630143
Aço - Inoxidável | Aço - Inoxidável | 62.2628 (kgCO₂) | 574.032 | 10.124 | 0.00128152
2 x Aço - Inoxidável | Aço - Inoxidável | 4.52499 (kgCO₂) | 41.7182 | 0.735771 | 0.0000931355
5 x Aço - Inoxidável | Aço - Inoxidável | 0.396881 (kgCO₂) | 3.65905 | 0.0645335 | 0.0000081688
2 x Aço - Inoxidável | Aço - Inoxidável | 69.1353 (kgCO₂) | 637.394 | 11.2415 | 0.00142298
Aço - Inoxidável | Aço - Inoxidável | 62.6708 (kgCO₂) | 577.794 | 10.1904 | 0.00128992
5 x Aço - Inoxidável | Aço - Inoxidável | 15.8459 (kgCO₂) | 146.091 | 2.57656 | 0.000326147
2 x Aço - Inoxidável | Aço - Inoxidável | 111.019 (kgCO₂) | 1023.54 | 18.0518 | 0.00228504
Aço - Inoxidável | Aço - Inoxidável | 98.9569 (kgCO₂) | 912.334 | 16.0906 | 0.00203678
5 x Aço - Inoxidável | Aço - Inoxidável | 24.5407 (kgCO₂) | 226.253 | 3.99036 | 0.000505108
2 x Aço - Inoxidável | Aço - Inoxidável | 363.131 (kgCO₂) | 3347.89 | 59.0457 | 0.00747414
Aço - Inoxidável | Aço - Inoxidável | 360.434 (kgCO₂) | 3323.03 | 58.6072 | 0.00741864
5 x Aço - Inoxidável | Aço - Inoxidável | 90.2752 (kgCO₂) | 832.294 | 14.6789 | 0.00185809
2 x Aço - Inoxidável | Aço - Inoxidável | 212.173 (kgCO₂) | 1956.13 | 34.4996 | 0.00436704
Aço - Inoxidável | Aço - Inoxidável | 215.802 (kgCO₂) | 1989.59 | 35.0898 | 0.00444175
5 x Aço - Inoxidável | Aço - Inoxidável | 53.9507 (kgCO₂) | 497.399 | 8.77247 | 0.00111044
Aço - Inoxidável | Aço - Inoxidável | 45.2066 (kgCO₂) | 416.783 | 7.35066 | 0.000930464
2 x Aço - Inoxidável | Aço - Inoxidável | 431.088 (kgCO₂) | 3974.42 | 70.0956 | 0.00887287
2 x Aço - Inoxidável | Aço - Inoxidável | 51.0094 (kgCO₂) | 470.282 | 8.29421 | 0.0010499
Aço - Inoxidável | Aço - Inoxidável | 45.7204 (kgCO₂) | 421.52 | 7.43421 | 0.000941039
Aço - Inoxidável | Aço - Inoxidável | 44.483 (kgCO₂) | 410.111 | 7.233 | 0.00091557
2 x Aço - Inoxidável | Aço - Inoxidável | 253.785 (kgCO₂) | 2339.77 | 41.2658 | 0.00522352
Aço - Inoxidável | Aço - Inoxidável | 44.4847 (kgCO₂) | 410.127 | 7.23328 | 0.000915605
Aço - Inoxidável | Aço - Inoxidável | 45.7187 (kgCO₂) | 421.504 | 7.43393 | 0.000941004
2 x Aço - Inoxidável | Aço - Inoxidável | 254.27 (kgCO₂) | 2344.25 | 41.3447 | 0.00523351
Aço - Inoxidável | Aço - Inoxidável | 45.0005 (kgCO₂) | 414.883 | 7.31716 | 0.000926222
Aço - Inoxidável | Aço - Inoxidável | 45.2029 (kgCO₂) | 416.748 | 7.35006 | 0.000930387
2 x Aço - Inoxidável | Aço - Inoxidável | 474.224 (kgCO₂) | 4372.12 | 77.1096 | 0.00976071
Aço - Inoxidável | Aço - Inoxidável | 45.7957 (kgCO₂) | 422.214 | 7.44646 | 0.00094259
2 x Aço - Inoxidável | Aço - Inoxidável | 734.113 (kgCO₂) | 6768.16 | 119.368 | 0.0151099
2 x Aço - Inoxidável | Aço - Inoxidável | 243.306 (kgCO₂) | 2243.16 | 39.5619 | 0.00500784
Aço - Inoxidável | Aço - Inoxidável | 35.4056 (kgCO₂) | 326.422 | 5.757 | 0.000728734
2 x Aço - Inoxidável | Aço - Inoxidável | 4.35944 (kgCO₂) | 40.1919 | 0.708852 | 0.000089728
5 x Aço - Inoxidável | Aço - Inoxidável | 0.381607 (kgCO₂) | 3.51823 | 0.0620499 | 0.00000785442
2 x Aço - Inoxidável | Aço - Inoxidável | 4.34731 (kgCO₂) | 40.0801 | 0.70688 | 0.0000894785
5 x Aço - Inoxidável | Aço - Inoxidável | 0.380497 (kgCO₂) | 3.508 | 0.0618695 | 0.00000783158
Aço - Inoxidável | Aço - Inoxidável | 35.4189 (kgCO₂) | 326.545 | 5.75917 | 0.000729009
2 x Aço - Inoxidável | Aço - Inoxidável | 246.964 (kgCO₂) | 2276.89 | 40.1567 | 0.00508313
Aço - Inoxidável | Aço - Inoxidável | 240.325 (kgCO₂) | 2215.68 | 39.0772 | 0.00494648
5 x Aço - Inoxidável | Aço - Inoxidável | 60.0812 (kgCO₂) | 553.919 | 9.7693 | 0.00123662
2 x Aço - Inoxidável | Aço - Inoxidável | 1105.79 (kgCO₂) | 10194.8 | 179.803 | 0.0227598
Aço - Inoxidável | Aço - Inoxidável | 1088.27 (kgCO₂) | 10033.3 | 176.955 | 0.0223994
5 x Aço - Inoxidável | Aço - Inoxidável | 272.391 (kgCO₂) | 2511.31 | 44.2912 | 0.00560649
2 x Aço - Inoxidável | Aço - Inoxidável | 247.467 (kgCO₂) | 2281.53 | 40.2386 | 0.0050935
Aço - Inoxidável | Aço - Inoxidável | 240.831 (kgCO₂) | 2220.34 | 39.1595 | 0.0049569
5 x Aço - Inoxidável | Aço - Inoxidável | 60.2077 (kgCO₂) | 555.086 | 9.78987 | 0.00123922

# IfcBuildingElementProxy: Banco Prça Ferro Madeira (35)
In: Pavimento Térreo
AC_Pset_RenovationAndPhasing - Renovation Status: Existing
Component Quantities - Component 1, Volume Componente (Líquido): 0 m3; Component 1, Volume do componente (Bruto): 0 m3

# IfcBuildingElementProxy: Cerca Colorida (20)
In: Pavimento Térreo
AC_Pset_RenovationAndPhasing - Renovation Status: Existing
Component Quantities - Component 1, Volume Componente (Líquido): 0 m3; Component 1, Volume do componente (Bruto): 0 m3

# IfcBuildingElementProxy: FALTA (100)
In: Pavimento Térreo
AC_Pset_RenovationAndPhasing - Renovation Status: Existing
Component Properties - Component 1, Tipo de Componente: Nenhum
Name | Component 1, Volume Componente (Líquido) (m3) = Component 1, Volume do componente (Bruto) (m3)
33 x Objeto-0055 | 0.000974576
31 x Objeto-0054 | 0
Objeto-0055 | 0.000554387
Objeto-0055 | 0.00055465
7 x Objeto-0044 | 0.00188754
6 x Objeto-0044 | 0.00152501
8 x Objeto-0044 | 0.00152928
2 x Objeto-0055 | 0.000555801
2 x Objeto-0055 | 0.000366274
7 x Objeto-0044 | 0.00189282
Objeto-0055 | 0.000598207
Objeto-0055 | 0.000366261

# IfcBuildingElementProxy: GENÉRICO - ESTRUTURAL, Viga-030
In: Pavimento Térreo
Material: GENÉRICO - ESTRUTURAL
AC_Pset_RenovationAndPhasing - Renovation Status: Existing
Component Properties - Component 1, Carbono Incorporado: 207.015 (kgCO₂); Component 1, Energia Incorporada: 2007.42 MJ; Component 1, Tipo de Componente: Nenhum
Component Quantities - Component 1, Massa: 1045.53 kg; Component 1, Volume Componente (Líquido): 0.454579 m3; Component 1, Volume do componente (Bruto): 0.454579 m3

# IfcBuildingElementProxy: IfcBuildingElementProxy, TREAD-003
In: Pavimento Térreo
Material: Concreto Armado - Pré-fabricado
AC_Pset_RenovationAndPhasing - Renovation Status: Existing
Component Properties - Component 1, Carbono Incorporado: 60.338 (kgCO₂); Component 1, Energia Incorporada: 580.94 MJ
Component Quantities - Component 1, Massa: 249.331 kg; Component 1, Volume Componente (Líquido): 0.103888 m3; Component 1, Volume do componente (Bruto): 0.103888 m3

# IfcBuildingElementProxy: Lixeira Reciclável0 (5)
In: Pavimento Térreo
AC_Pset_RenovationAndPhasing - Renovation Status: Existing
Component Quantities - Component 1, Volume Componente (Líquido): 0 m3; Component 1, Volume do componente (Bruto): 0 m3

# IfcBuildingElementProxy: MULTI EXERCITADOR, Objeto-0089
In: Pavimento Térreo
AC_Pset_RenovationAndPhasing - Renovation Status: Existing
Component Quantities - Component 1, Volume Componente (Líquido): 0 m3; Component 1, Volume do componente (Bruto): 0 m3

# IfcBuildingElementProxy: Marcação PIso Def Fisico, Objeto-0003
In: Pavimento Térreo
Material: Concreto
AC_Pset_RenovationAndPhasing - Renovation Status: Existing
Component Properties - Component 1, Carbono Incorporado: 4.54157 (kgCO₂); Component 1, Energia Incorporada: 31.409 MJ
Component Quantities - Component 1, Massa: 42.4446 kg; Component 1, Volume Componente (Líquido): 0.0235803 m3; Component 1, Volume do componente (Bruto): 0.0235803 m3

# IfcBuildingElementProxy: Musculação Pernas, Objeto-0089
In: Pavimento Térreo
AC_Pset_RenovationAndPhasing - Renovation Status: Existing
Component Quantities - Component 1, Volume Componente (Líquido): 0 m3; Component 1, Volume do componente (Bruto): 0 m3

# IfcBuildingElementProxy: Piso Direcional 27 (864)
In: Pavimento Térreo
AC_Pset_RenovationAndPhasing - Renovation Status: Existing
Component Quantities - Component 1, Volume Componente (Líquido): 0 m3; Component 1, Volume do componente (Bruto): 0 m3

# IfcBuildingElementProxy: Piso tatil alerta 22 (219)
In: Pavimento Térreo
AC_Pset_RenovationAndPhasing - Renovation Status: Existing
Component Quantities - Component 1, Volume Componente (Líquido): 0 m3; Component 1, Volume do componente (Bruto): 0 m3

# IfcBuildingElementProxy: Placa vertical idoso (2)
In: Pavimento Térreo
AC_Pset_RenovationAndPhasing - Renovation Status: Existing
Component Quantities - Component 1, Volume Componente (Líquido): 0 m3; Component 1, Volume do componente (Bruto): 0 m3

# IfcBuildingElementProxy: Rampa Direta 25 (3)
In: Pavimento Térreo
Material: Concreto - Estrutural
AC_Pset_RenovationAndPhasing - Renovation Status: Existing
Name | Component 1, Carbono Incorporado | Component 1, Energia Incorporada (MJ) | Component 1, Massa (kg) | Component 1, Volume Componente (Líquido) (m3) = Component 1, Volume do componente (Bruto) (m3)
Objeto-0001 | 294.261 (kgCO₂) | 2853.44 | 1486.17 | 0.64616
Objeto-0001 | 224.843 (kgCO₂) | 2180.3 | 1135.57 | 0.493726
Objeto-0088 | 394.82 (kgCO₂) | 3828.56 | 1994.04 | 0.866974

# IfcBuildingElementProxy: Simulador de caminhada, Objeto-0089
In: Pavimento Térreo
AC_Pset_RenovationAndPhasing - Renovation Status: Existing
Component Quantities - Component 1, Volume Componente (Líquido): 0 m3; Component 1, Volume do componente (Bruto): 0 m3

# IfcBuildingElementProxy: Tela metalica1 (49)
In: Pavimento Térreo
AC_Pset_RenovationAndPhasing - Renovation Status: Existing
Component Quantities - Component 1, Volume Componente (Líquido): 0 m3; Component 1, Volume do componente (Bruto): 0 m3

# IfcBuildingElementProxy: Trave Futebol0 (2)
In: Pavimento Térreo
Classification: Proxy Elemento Construtivo (Classificação ARCHICAD)
AC_Pset_RenovationAndPhasing - Renovation Status: Existing
Component Quantities - Component 1, Volume Componente (Líquido): 0 m3; Component 1, Volume do componente (Bruto): 0 m3

# IfcBuildingElementProxy: Tubo 25 (2)
In: Pavimento Térreo
AC_Pset_RenovationAndPhasing - Renovation Status: Existing
Component Quantities - Component 1, Volume Componente (Líquido): 0.00388229 m3; Component 1, Volume do componente (Bruto): 0.00388229 m3

# IfcColumn: Alumínio 50 x 50 (44)
In: Pavimento Térreo
Classification: Pilar (Classificação ARCHICAD); Material: Alumínio
AC_Pset_RenovationAndPhasing - Renovation Status: Existing
Pset_ColumnCommon - Reference: Alumínio 50 x 50
Component Properties - Component 1, Tipo de Componente: Núcleo
BaseQuantities - Width: 50 mm; Depth: 50 mm; CrossSectionArea: 0.0025 m2
Component Quantities - Component 1, Espessura do Componente: 50 mm; Component 1, Altura do Componente Retangular: 50 mm; Component 1, Largura do Componente Retangular: 50 mm; Component 1, Área de Seção Transversal do Componente: 0.0025 m2
Name | Component 1, Carbono Incorporado | Component 1, Energia Incorporada (MJ) | Length (mm) | OuterSurfaceArea (m2) | TotalSurfaceArea (m2) = GrossSurfaceArea (m2) | GrossVolume (m3) = NetVolume (m3) = Component 1, Volume Componente (Líquido) (m3) = Component 1, Volume do componente (Bruto) (m3) | Component 1, Massa (kg)
3 x Pil-016 | 234.976 (kgCO₂) | 3976.13 | 3682.02 | 0.734665 | 0.735799 | 0.00916159 | 25.6524
9 x Pil-016 | 197.826 (kgCO₂) | 3347.49 | 3085.25 | 0.61705 | 0.61955 | 0.00771312 | 21.5967
3 x Pil-016 | 136.762 (kgCO₂) | 2314.2 | 2150.29 | 0.428319 | 0.429453 | 0.00533225 | 14.9303
7 x Pil-016 | 235.156 (kgCO₂) | 3979.16 | 3698.32 | 0.736575 | 0.737709 | 0.00916858 | 25.672
9 x Pil-016 | 198.772 (kgCO₂) | 3363.5 | 3100 | 0.62 | 0.625 | 0.00775 | 21.7
2 x Pil-016 | 247.157 (kgCO₂) | 4182.24 | 3871.99 | 0.772659 | 0.773793 | 0.00963651 | 26.9822
2 x Pil-016 | 197.838 (kgCO₂) | 3347.7 | 3085.44 | 0.617088 | 0.619588 | 0.0077136 | 21.5981
Pil-016 | 235.57 (kgCO₂) | 3986.17 | 3698.32 | 0.73726 | 0.738368 | 0.00918473 | 25.7173
Pil-016 | 247.164 (kgCO₂) | 4182.36 | 3871.99 | 0.772669 | 0.773809 | 0.00963677 | 26.983
3 x Pil-016 | 236.035 (kgCO₂) | 3994.04 | 3698.32 | 0.737946 | 0.73909 | 0.00920285 | 25.768
2 x Pil-016 | 128.325 (kgCO₂) | 2171.43 | 2001.32 | 0.400264 | 0.402764 | 0.0050033 | 14.0092
Pil-016 | 186.118 (kgCO₂) | 3149.38 | 2902.65 | 0.58053 | 0.58303 | 0.00725663 | 20.3186
Pil-016 | 128.866 (kgCO₂) | 2180.59 | 2016.51 | 0.402628 | 0.403628 | 0.00502441 | 14.0684

# IfcColumn: Alumínio D30 (4)
In: Pavimento Térreo
Classification: Pilar (Classificação ARCHICAD); Material: Alumínio
AC_Pset_RenovationAndPhasing - Renovation Status: Existing
Pset_ColumnCommon - Reference: Alumínio D30
Component Properties - Component 1, Tipo de Componente: Núcleo
BaseQuantities - Width: 30 mm; Depth: 30 mm; CrossSectionArea: 0.000706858 m2
Component Quantities - Component 1, Espessura do Componente: 30 mm; Component 1, Área de Seção Transversal do Componente: 0.000706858 m2
Name | Component 1, Carbono Incorporado | Component 1, Energia Incorporada (MJ) | Length (mm) | OuterSurfaceArea (m2) | TotalSurfaceArea (m2) = GrossSurfaceArea (m2) | GrossVolume (m3) = NetVolume (m3) = Component 1, Volume Componente (Líquido) (m3) = Component 1, Volume do componente (Bruto) (m3) | Component 1, Massa (kg)
2 x Pil-016 | 34.8477 (kgCO₂) | 589.671 | 2037.68 | 0.188122 | 0.189472 | 0.00135869 | 3.80433
Pil-016 | 35.4903 (kgCO₂) | 600.546 | 2050 | 0.191008 | 0.191683 | 0.00138375 | 3.87449
Pil-016 | 35.4333 (kgCO₂) | 599.581 | 2046.7 | 0.190701 | 0.192051 | 0.00138152 | 3.86826

# IfcColumn: Alumínio D39 (9)
In: Pavimento Térreo
Classification: Pilar (Classificação ARCHICAD); Material: Alumínio
AC_Pset_RenovationAndPhasing - Renovation Status: Existing
Pset_ColumnCommon - Reference: Alumínio D39
Component Properties - Component 1, Tipo de Componente: Núcleo
BaseQuantities - Width: 39.0034 mm; Depth: 39.0034 mm; CrossSectionArea: 0.0011948 m2
Component Quantities - Component 1, Espessura do Componente: 39.0034 mm; Component 1, Área de Seção Transversal do Componente: 0.0011948 m2
Name | Component 1, Carbono Incorporado | Component 1, Energia Incorporada (MJ) | Length (mm) | OuterSurfaceArea (m2) | TotalSurfaceArea (m2) = GrossSurfaceArea (m2) | GrossVolume (m3) = NetVolume (m3) = Component 1, Volume Componente (Líquido) (m3) = Component 1, Volume do componente (Bruto) (m3) | Component 1, Massa (kg)
Pil-016 | 59.4823 (kgCO₂) | 1006.52 | 2046.7 | 0.247028 | 0.248189 | 0.00231918 | 6.49371
Pil-016 | 61.9354 (kgCO₂) | 1048.03 | 2116.5 | 0.256389 | 0.258671 | 0.00241482 | 6.7615
2 x Pil-016 | 59.1734 (kgCO₂) | 1001.3 | 2046.7 | 0.246123 | 0.246446 | 0.00230714 | 6.45998
3 x Pil-016 | 62.924 (kgCO₂) | 1064.76 | 2150.29 | 0.260481 | 0.261622 | 0.00245337 | 6.86943
Pil-016 | 62.0764 (kgCO₂) | 1050.42 | 2132.96 | 0.257527 | 0.258818 | 0.00242032 | 6.7769
Pil-016 | 60.1217 (kgCO₂) | 1017.34 | 2066.66 | 0.248901 | 0.250834 | 0.00234411 | 6.56351

# IfcColumn: Aço - Inoxidável 80 x 80 (24)
In: Pavimento Térreo
Classification: Pilar (Classificação ARCHICAD); Material: Aço - Inoxidável
AC_Pset_RenovationAndPhasing - Renovation Status: Existing
Pset_ColumnCommon - Reference: Aço - Inoxidável 80 x 80
Component Properties - Component 1, Tipo de Componente: Núcleo
BaseQuantities - Width: 80 mm; Depth: 80 mm; CrossSectionArea: 0.0064 m2
Component Quantities - Component 1, Espessura do Componente: 80 mm; Component 1, Altura do Componente Retangular: 80 mm; Component 1, Largura do Componente Retangular: 80 mm; Component 1, Área de Seção Transversal do Componente: 0.0064 m2
Name | Component 1, Carbono Incorporado | Component 1, Energia Incorporada (MJ) | Length (mm) | OuterSurfaceArea (m2) | TotalSurfaceArea (m2) = GrossSurfaceArea (m2) | GrossVolume (m3) = NetVolume (m3) = Component 1, Volume Componente (Líquido) (m3) = Component 1, Volume do componente (Bruto) (m3) | Component 1, Massa (kg)
21 x Pil-019 | 373.133 (kgCO₂) | 3440.1 | 1200 | 0.384 | 0.3968 | 0.00768 | 60.672
Pil-019 | 364.228 (kgCO₂) | 3358 | 1171.36 | 0.374835 | 0.387635 | 0.00749671 | 59.224
Pil-019 | 666.101 (kgCO₂) | 6141.12 | 2147.1 | 0.686286 | 0.698102 | 0.01371 | 108.309
Pil-019 | 668.429 (kgCO₂) | 6162.59 | 2155.29 | 0.688679 | 0.700687 | 0.0137579 | 108.688

# IfcFurnishingElement: Porta Bicicletas 02 25 (2)
In: Pavimento Térreo
Classification: Mobiliário (Classificação ARCHICAD)
AC_Pset_RenovationAndPhasing - Renovation Status: Existing
Component Quantities - Component 1, Volume Componente (Líquido): 0.01568 m3; Component 1, Volume do componente (Bruto): 0.01568 m3

# IfcFurnishingElement: rede volei, Objeto-0071
In: Pavimento Térreo
Classification: Mobiliário (Classificação ARCHICAD)
AC_Pset_RenovationAndPhasing - Renovation Status: Existing
Component Quantities - Component 1, Volume Componente (Líquido): 0 m3; Component 1, Volume do componente (Bruto): 0 m3

# IfcMember: IfcMember (51)
In: Pavimento Térreo
AC_Pset_RenovationAndPhasing - Renovation Status: Existing
Name | Classification | Material | Component 1, Carbono Incorporado | Component 1, Energia Incorporada (MJ) | GrossVolume (m3) = NetVolume (m3) = Component 1, Volume Componente (Líquido) (m3) = Component 1, Volume do componente (Bruto) (m3) | Component 1, Massa (kg)
Lance - 014 | Estrutura de Escada (Classificação ARCHICAD) | Concreto - Estrutural | 604.079 (kgCO₂) | 5857.74 | 1.32648 | 3050.9
Piso Esc. - 102 | Acabamento Piso (Classificação ARCHICAD) | Concreto Armado - Pré-fabricado | 7.55795 (kgCO₂) | 72.7687 | 0.013013 | 31.2312
Piso Esc. - 103 | Acabamento Piso (Classificação ARCHICAD) | Concreto Armado - Pré-fabricado | 7.55795 (kgCO₂) | 72.7687 | 0.013013 | 31.2312
Piso Esc. - 104 | Acabamento Piso (Classificação ARCHICAD) | Concreto Armado - Pré-fabricado | 7.55795 (kgCO₂) | 72.7687 | 0.013013 | 31.2312
Piso Esc. - 105 | Acabamento Piso (Classificação ARCHICAD) | Concreto Armado - Pré-fabricado | 7.55795 (kgCO₂) | 72.7687 | 0.013013 | 31.2312
Piso Esc. - 106 | Acabamento Piso (Classificação ARCHICAD) | Concreto Armado - Pré-fabricado | 7.55795 (kgCO₂) | 72.7687 | 0.013013 | 31.2312
Piso Esc. - 107 | Acabamento Piso (Classificação ARCHICAD) | Concreto Armado - Pré-fabricado | 7.55795 (kgCO₂) | 72.7687 | 0.013013 | 31.2312
Piso Esc. - 108 | Acabamento Piso (Classificação ARCHICAD) | Concreto Armado - Pré-fabricado | 7.55795 (kgCO₂) | 72.7687 | 0.013013 | 31.2312
Piso Esc. - 109 | Acabamento Piso (Classificação ARCHICAD) | Concreto Armado - Pré-fabricado | 7.55795 (kgCO₂) | 72.7687 | 0.013013 | 31.2312
Piso Esc. - 110 | Acabamento Piso (Classificação ARCHICAD) | Concreto Armado - Pré-fabricado | 7.55795 (kgCO₂) | 72.7687 | 0.013013 | 31.2312
Piso Esc. - 111 | Acabamento Piso (Classificação ARCHICAD) | Concreto Armado - Pré-fabricado | 7.55795 (kgCO₂) | 72.7687 | 0.013013 | 31.2312
Piso Esc. - 112 | Acabamento Piso (Classificação ARCHICAD) | Concreto Armado - Pré-fabricado | 7.55795 (kgCO₂) | 72.7687 | 0.013013 | 31.2312
Piso Esc. - 114 | Acabamento Piso (Classificação ARCHICAD) | Concreto Armado - Pré-fabricado | 7.55784 (kgCO₂) | 72.7677 | 0.0130128 | 31.2308
Lance - 005 | Estrutura de Escada (Classificação ARCHICAD) | Concreto - Estrutural | 36.5219 (kgCO₂) | 354.151 | 0.0801973 | 184.454
Piso Esc. - 034 | Acabamento Piso (Classificação ARCHICAD) | Concreto Armado - Pré-fabricado | 7.10028 (kgCO₂) | 68.3622 | 0.012225 | 29.34
Lance - 014 | Estrutura de Escada (Classificação ARCHICAD) | Concreto - Estrutural | 598.115 (kgCO₂) | 5799.9 | 1.31338 | 3020.78
Piso Esc. - 102 | Acabamento Piso (Classificação ARCHICAD) | Concreto Armado - Pré-fabricado | 7.47562 (kgCO₂) | 71.976 | 0.0128713 | 30.891
Piso Esc. - 103 | Acabamento Piso (Classificação ARCHICAD) | Concreto Armado - Pré-fabricado | 7.47696 (kgCO₂) | 71.9889 | 0.0128736 | 30.8965
Piso Esc. - 104 | Acabamento Piso (Classificação ARCHICAD) | Concreto Armado - Pré-fabricado | 7.4783 (kgCO₂) | 72.0018 | 0.0128759 | 30.9021
Piso Esc. - 105 | Acabamento Piso (Classificação ARCHICAD) | Concreto Armado - Pré-fabricado | 7.47964 (kgCO₂) | 72.0147 | 0.0128782 | 30.9076
Piso Esc. - 106 | Acabamento Piso (Classificação ARCHICAD) | Concreto Armado - Pré-fabricado | 7.48098 (kgCO₂) | 72.0276 | 0.0128805 | 30.9131
Piso Esc. - 107 | Acabamento Piso (Classificação ARCHICAD) | Concreto Armado - Pré-fabricado | 7.48232 (kgCO₂) | 72.0405 | 0.0128828 | 30.9187
Piso Esc. - 108 | Acabamento Piso (Classificação ARCHICAD) | Concreto Armado - Pré-fabricado | 7.48365 (kgCO₂) | 72.0534 | 0.0128851 | 30.9242
Piso Esc. - 109 | Acabamento Piso (Classificação ARCHICAD) | Concreto Armado - Pré-fabricado | 7.48499 (kgCO₂) | 72.0662 | 0.0128874 | 30.9297
Piso Esc. - 110 | Acabamento Piso (Classificação ARCHICAD) | Concreto Armado - Pré-fabricado | 7.48633 (kgCO₂) | 72.0791 | 0.0128897 | 30.9352
Piso Esc. - 111 | Acabamento Piso (Classificação ARCHICAD) | Concreto Armado - Pré-fabricado | 7.48767 (kgCO₂) | 72.092 | 0.012892 | 30.9408
Piso Esc. - 112 | Acabamento Piso (Classificação ARCHICAD) | Concreto Armado - Pré-fabricado | 7.48901 (kgCO₂) | 72.1049 | 0.0128943 | 30.9463
Piso Esc. - 114 | Acabamento Piso (Classificação ARCHICAD) | Concreto Armado - Pré-fabricado | 7.49026 (kgCO₂) | 72.117 | 0.0128965 | 30.9515
Lance - 011 | Estrutura de Escada (Classificação ARCHICAD) | Concreto - Estrutural | 679.878 (kgCO₂) | 6592.75 | 1.49292 | 3433.72
Piso Esc. - 066 | Acabamento Piso (Classificação ARCHICAD) | Concreto Armado - Pré-fabricado | 8.88624 (kgCO₂) | 85.5576 | 0.0153 | 36.72
Piso Esc. - 067 | Acabamento Piso (Classificação ARCHICAD) | Concreto Armado - Pré-fabricado | 8.88624 (kgCO₂) | 85.5576 | 0.0153 | 36.72
Piso Esc. - 068 | Acabamento Piso (Classificação ARCHICAD) | Concreto Armado - Pré-fabricado | 8.88624 (kgCO₂) | 85.5576 | 0.0153 | 36.72
Piso Esc. - 069 | Acabamento Piso (Classificação ARCHICAD) | Concreto Armado - Pré-fabricado | 8.88624 (kgCO₂) | 85.5576 | 0.0153 | 36.72
Piso Esc. - 070 | Acabamento Piso (Classificação ARCHICAD) | Concreto Armado - Pré-fabricado | 8.88624 (kgCO₂) | 85.5576 | 0.0153 | 36.72
Piso Esc. - 071 | Acabamento Piso (Classificação ARCHICAD) | Concreto Armado - Pré-fabricado | 8.88624 (kgCO₂) | 85.5576 | 0.0153 | 36.72
Piso Esc. - 072 | Acabamento Piso (Classificação ARCHICAD) | Concreto Armado - Pré-fabricado | 8.88624 (kgCO₂) | 85.5576 | 0.0153 | 36.72
Piso Esc. - 073 | Acabamento Piso (Classificação ARCHICAD) | Concreto Armado - Pré-fabricado | 8.88624 (kgCO₂) | 85.5576 | 0.0153 | 36.72
Piso Esc. - 074 | Acabamento Piso (Classificação ARCHICAD) | Concreto Armado - Pré-fabricado | 8.88624 (kgCO₂) | 85.5576 | 0.0153 | 36.72
Piso Esc. - 075 | Acabamento Piso (Classificação ARCHICAD) | Concreto Armado - Pré-fabricado | 8.88624 (kgCO₂) | 85.5576 | 0.0153 | 36.72
Piso Esc. - 076 | Acabamento Piso (Classificação ARCHICAD) | Concreto Armado - Pré-fabricado | 8.88624 (kgCO₂) | 85.5576 | 0.0153 | 36.72
Piso Esc. - 077 | Acabamento Piso (Classificação ARCHICAD) | Concreto Armado - Pré-fabricado | 8.88624 (kgCO₂) | 85.5576 | 0.0153 | 36.72
Lance - 001 | Estrutura de Escada (Classificação ARCHICAD) | Concreto - Estrutural | 376.156 (kgCO₂) | 3647.57 | 0.825991 | 1899.78
Lance - 009 | Estrutura de Escada (Classificação ARCHICAD) | Concreto - Estrutural | 188.708 (kgCO₂) | 1829.9 | 0.41438 | 953.073
Lance - 010 | Estrutura de Escada (Classificação ARCHICAD) | Concreto - Estrutural | 252.113 (kgCO₂) | 2444.73 | 0.553608 | 1273.3
Piso Esc. - 059 | Acabamento Piso (Classificação ARCHICAD) | Concreto Armado - Pré-fabricado | 8.88624 (kgCO₂) | 85.5576 | 0.0153 | 36.72
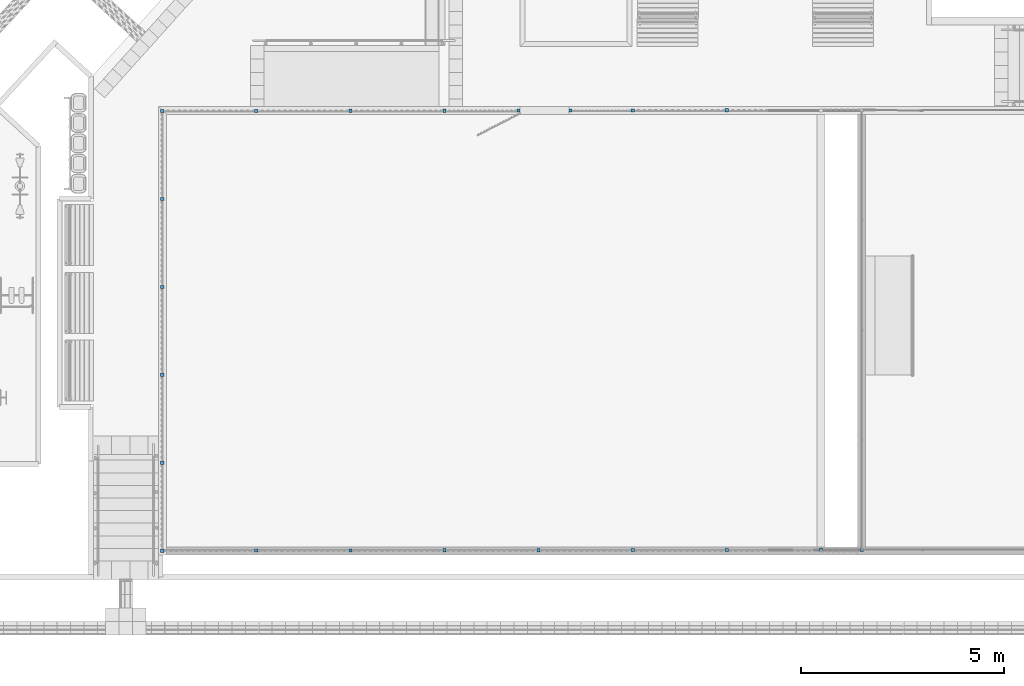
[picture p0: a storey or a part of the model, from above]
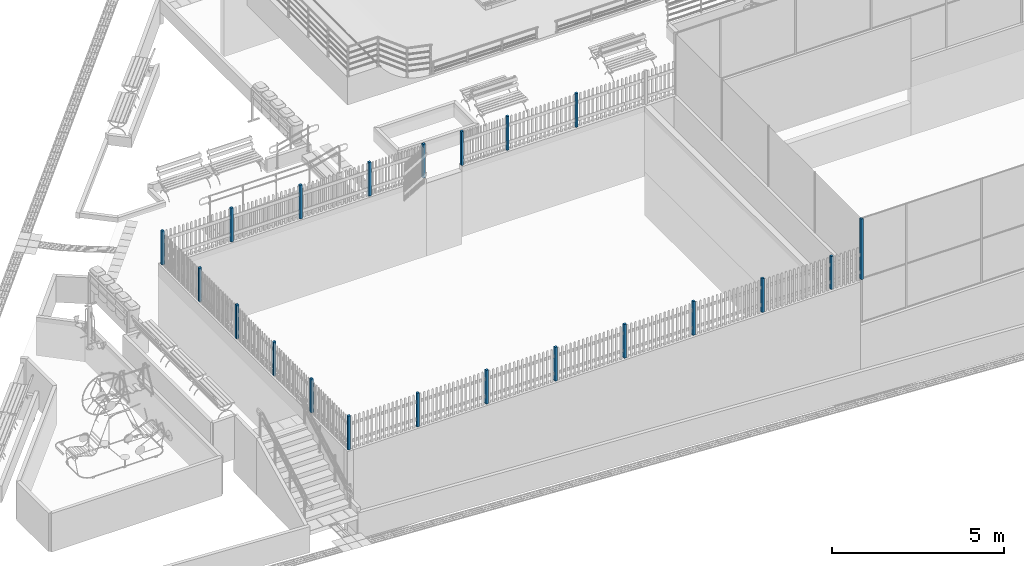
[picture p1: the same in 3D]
Properties of the parts of a building model (IFC2X3), part 2 of 2

# IfcMember: IfcMember (51)
Name | Classification | Material | Component 1, Carbono Incorporado | Component 1, Energia Incorporada (MJ) | GrossVolume (m3) = NetVolume (m3) = Component 1, Volume Componente (Líquido) (m3) = Component 1, Volume do componente (Bruto) (m3) | Component 1, Massa (kg)
Piso Esc. - 060 | Acabamento Piso (Classificação ARCHICAD) | Concreto Armado - Pré-fabricado | 8.88624 (kgCO₂) | 85.5576 | 0.0153 | 36.72
Piso Esc. - 061 | Acabamento Piso (Classificação ARCHICAD) | Concreto Armado - Pré-fabricado | 8.88624 (kgCO₂) | 85.5576 | 0.0153 | 36.72
Piso Esc. - 062 | Acabamento Piso (Classificação ARCHICAD) | Concreto Armado - Pré-fabricado | 8.88624 (kgCO₂) | 85.5576 | 0.0153 | 36.72
Piso Esc. - 063 | Acabamento Piso (Classificação ARCHICAD) | Concreto Armado - Pré-fabricado | 8.88624 (kgCO₂) | 85.5576 | 0.0153 | 36.72
Piso Esc. - 064 | Acabamento Piso (Classificação ARCHICAD) | Concreto Armado - Pré-fabricado | 8.88624 (kgCO₂) | 85.5576 | 0.0153 | 36.72
Piso Esc. - 065 | Acabamento Piso (Classificação ARCHICAD) | Concreto Armado - Pré-fabricado | 8.88624 (kgCO₂) | 85.5576 | 0.0153 | 36.72

# IfcRailing: Tipo de Guarda-Corpo (23)
In: Pavimento Térreo
Classification: Guarda-Corpo (Classificação ARCHICAD)
AC_Pset_RenovationAndPhasing - Renovation Status: Existing
Name | GrossVolume (m3) = NetVolume (m3) | Length (mm)
Guarda-Corpo - 001 | 0.00688925 | 1146.56
4 x Guarda-Corpo - 002 | 0.00870811 | 3550
Guarda-Corpo - 004 | 0.178403 | 27559.2
Guarda-Corpo - 001 | 0.0490887 | 12078.5
Guarda-Corpo - 001 | 0.0187246 | 4462.74
Guarda-Corpo - 001 | 0.0141747 | 3120.46
Guarda-Corpo - 001 | 0.0140462 | 3069.5
Guarda-Corpo - 001 | 0.0490866 | 12077
Guarda-Corpo - 001 | 0.042166 | 6401.2
2 x Guarda-Corpo - 001 | 0.0146292 | 3291.36
Guarda-Corpo - 001 | 0.0270966 | 3200
Guarda-Corpo - 001 | 0.0164998 | 4052.92
Guarda-Corpo - 002 | 0.081899 | 12140.7
Guarda-Corpo - 002 | 0.0217043 | 7777.82
Guarda-Corpo - 002 | 0.0181486 | 4234.89
Guarda-Corpo - 001 | 0.0181686 | 4242.82
Guarda-Corpo - 001 | 0.03073 | 7833.49
Guarda-Corpo - 003 | 0.0596413 | 16425.5
Guarda-Corpo - 001 | 0.169326 | 25777.9

# IfcSlab: Areia 100 (2)
In: Pavimento Térreo
Type - PredefinedType: FLOOR
Classification: Laje (Classificação ARCHICAD); Material: Areia 100 mm
AC_Pset_RenovationAndPhasing - Renovation Status: Existing
Pset_SlabCommon - LoadBearing: no
Component Properties - Component 1, Tipo de Componente: Nenhum
BaseQuantities - Width: 100 mm
Component Quantities - Component 1, Espessura do Componente: 100 mm
Name | Component 1, Carbono Incorporado | Component 1, Energia Incorporada (MJ) | Perimeter (mm) | GrossArea (m2) = NetArea (m2) | GrossVolume (m3) = NetVolume (m3) = Component 1, Volume Componente (Líquido) (m3) = Component 1, Volume do componente (Bruto) (m3) | Component 1, Massa (kg) | Component 1, Área de Componente Projetada (Líquida) (m2) = Component 1, Área de Componente Projetada (Bruta) (m2)
Laje-036 | 1329.97 (kgCO₂) | 18165.5 | 53001.7 | 147.447 | 14.7447 | 32438.4 | 147.447
Laje-036 | 1822.62 (kgCO₂) | 24894.4 | 59274 | 202.064 | 20.2065 | 44454.3 | 202.066

# IfcSlab: Concreto 10 (42)
In: Pavimento Térreo
Type - PredefinedType: FLOOR
Classification: Laje (Classificação ARCHICAD); Material: Concreto 10 mm
AC_Pset_RenovationAndPhasing - Renovation Status: Existing
Pset_SlabCommon - LoadBearing: no
Component Properties - Component 1, Tipo de Componente: Nenhum
BaseQuantities - Width: 10 mm
Component Quantities - Component 1, Espessura do Componente: 10 mm
Name | Component 1, Carbono Incorporado | Component 1, Energia Incorporada (MJ) | Perimeter (mm) | GrossArea (m2) = NetArea (m2) = Component 1, Área de Componente Projetada (Líquida) (m2) = Component 1, Área de Componente Projetada (Bruta) (m2) | GrossVolume (m3) = NetVolume (m3) = Component 1, Volume Componente (Líquido) (m3) = Component 1, Volume do componente (Bruto) (m3) | Component 1, Massa (kg)
2 x Laje-023 | 0.962981 (kgCO₂) | 6.65987 | 10199.8 | 0.49999 | 0.0049999 | 8.99982
Laje-023 | 0.972442 (kgCO₂) | 6.7253 | 10371.6 | 0.504902 | 0.00504902 | 9.08824
7 x Laje-023 | 0.963 (kgCO₂) | 6.66 | 10200 | 0.5 | 0.005 | 9
Laje-023 | 0.972528 (kgCO₂) | 6.7259 | 10298.9 | 0.504947 | 0.00504947 | 9.08905
Laje-023 | 0.971322 (kgCO₂) | 6.71756 | 10286.4 | 0.504321 | 0.00504321 | 9.07778
Laje-023 | 0.944603 (kgCO₂) | 6.53277 | 10200 | 0.490448 | 0.00490448 | 8.82806
Laje-023 | 0.962878 (kgCO₂) | 6.65916 | 10198.7 | 0.499937 | 0.00499937 | 8.99886
3 x Laje-023 | 0.97263 (kgCO₂) | 6.7266 | 10300 | 0.505 | 0.00505 | 9.09
Laje-023 | 0.972713 (kgCO₂) | 6.72717 | 10300.9 | 0.505043 | 0.00505043 | 9.09078
Laje-023 | 0.97259 (kgCO₂) | 6.72632 | 10299.3 | 0.504979 | 0.00504979 | 9.08962
Laje-023 | 0.973937 (kgCO₂) | 6.73564 | 10313.6 | 0.505678 | 0.00505678 | 9.10221
Laje-023 | 0.972547 (kgCO₂) | 6.72602 | 10299.1 | 0.504957 | 0.00504957 | 9.08922
Laje-023 | 0.972718 (kgCO₂) | 6.72721 | 10300.9 | 0.505045 | 0.00505045 | 9.09082
Laje-023 | 1.89254 (kgCO₂) | 13.0886 | 20229.2 | 0.982628 | 0.00982628 | 17.6873
Laje-023 | 0.972731 (kgCO₂) | 6.7273 | 10301.1 | 0.505053 | 0.00505053 | 9.09095
Laje-023 | 0.971703 (kgCO₂) | 6.72019 | 10290.4 | 0.504519 | 0.00504519 | 9.08134
Laje-023 | 0.962756 (kgCO₂) | 6.65831 | 10200 | 0.499873 | 0.00499873 | 8.99772
Laje-023 | 0.973556 (kgCO₂) | 6.733 | 10309.6 | 0.505481 | 0.00505481 | 9.09865
Laje-023 | 0.962974 (kgCO₂) | 6.65982 | 10199.8 | 0.499986 | 0.00499986 | 8.99976
Laje-023 | 0.962941 (kgCO₂) | 6.65959 | 10199.8 | 0.49997 | 0.0049997 | 8.99945
Laje-023 | 0.962948 (kgCO₂) | 6.65964 | 10199.8 | 0.499973 | 0.00499973 | 8.99951
Laje-023 | 0.962954 (kgCO₂) | 6.65968 | 10199.8 | 0.499976 | 0.00499976 | 8.99957
Laje-023 | 0.962961 (kgCO₂) | 6.65973 | 10199.8 | 0.49998 | 0.0049998 | 8.99963
Laje-023 | 0.962967 (kgCO₂) | 6.65977 | 10199.8 | 0.499983 | 0.00499983 | 8.9997
Laje-023 | 0.560738 (kgCO₂) | 3.878 | 5615.66 | 0.291141 | 0.00291141 | 5.24054
Laje-023 | 1.23326 (kgCO₂) | 8.5291 | 13075.4 | 0.640323 | 0.00640323 | 11.5258
Laje-031 | 0.0249198 (kgCO₂) | 0.172343 | 425.988 | 0.0129386 | 0.000129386 | 0.232895
Laje-030 | 0.00807734 (kgCO₂) | 0.055862 | 384.077 | 0.00419384 | 0.0000419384 | 0.0754892
Laje-029 | 0.00791919 (kgCO₂) | 0.0547682 | 432.51 | 0.00411173 | 0.0000411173 | 0.0740111
Laje-028 | 0.00809599 (kgCO₂) | 0.0559909 | 433.731 | 0.00420352 | 0.0000420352 | 0.0756634
Laje-027 | 0.00156733 (kgCO₂) | 0.0108395 | 117.196 | 0.000813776 | 0.00000813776 | 0.014648
Laje-026 | 0.0155025 (kgCO₂) | 0.107213 | 712.141 | 0.00804905 | 0.0000804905 | 0.144883
Laje-025 | 0.207788 (kgCO₂) | 1.43704 | 3474.54 | 0.107886 | 0.00107886 | 1.94195

# IfcSlab: Concreto 100 (8)
In: Pavimento Térreo
Type - PredefinedType: FLOOR
Classification: Laje (Classificação ARCHICAD); Material: Concreto 100 mm
AC_Pset_RenovationAndPhasing - Renovation Status: Existing
Pset_SlabCommon - LoadBearing: no
Component Properties - Component 1, Tipo de Componente: Nenhum
BaseQuantities - Width: 100 mm
Component Quantities - Component 1, Espessura do Componente: 100 mm
Name | Component 1, Carbono Incorporado | Component 1, Energia Incorporada (MJ) | Perimeter (mm) | GrossArea (m2) | NetArea (m2) | GrossVolume (m3) | NetVolume (m3) = Component 1, Volume Componente (Líquido) (m3) | Component 1, Massa (kg) | Component 1, Área de Componente Projetada (Líquida) (m2) | Component 1, Área de Componente Projetada (Bruta) (m2) | Component 1, Volume do componente (Bruto) (m3)
Laje-036 | 707.248 (kgCO₂) | 4891.25 | 41605.1 | 36.7211 | 36.7211 | 3.67211 | 3.67211 | 6609.79 | 36.7212 | 36.7212 | 3.67211
Laje-036 | 4300.97 (kgCO₂) | 29745 | 83137.2 | 296.593 | 223.313 | 29.6591 | 22.3311 | 40195.9 | 223.313 | 293.037 | 29.3035
Laje-036 | 311.475 (kgCO₂) | 2154.12 | 21037.7 | 16.1721 | 16.1721 | 1.61721 | 1.61721 | 2910.98 | 16.1721 | 16.1721 | 1.61721
Laje-036 | 275.422 (kgCO₂) | 1904.79 | 19345 | 14.3002 | 14.3002 | 1.43002 | 1.43002 | 2574.04 | 14.3002 | 14.3002 | 1.43002
Laje-036 | 1152.9 (kgCO₂) | 7973.3 | 47109.8 | 65.8656 | 59.8596 | 6.58656 | 5.98596 | 10774.7 | 59.8596 | 65.8656 | 6.58656
Laje-036 | 3277.16 (kgCO₂) | 22664.5 | 53270.1 | 170.154 | 170.154 | 17.0154 | 17.0154 | 30627.7 | 170.154 | 170.154 | 17.0154
Laje-036 | 3470 (kgCO₂) | 23998.1 | 60851.4 | 179.685 | 179.685 | 18.0166 | 18.0166 | 32429.9 | 180.705 | 180.705 | 18.0166
Laje-036 | 12267 (kgCO₂) | 84837.5 | 105462 | 636.918 | 636.918 | 63.6918 | 63.6918 | 114645 | 636.918 | 636.918 | 63.6918

# IfcSlab: Concreto 122, Laje-037
In: Pavimento Térreo
Type - PredefinedType: FLOOR
Classification: Laje (Classificação ARCHICAD); Material: Concreto 122.313 mm
AC_Pset_RenovationAndPhasing - Renovation Status: Existing
Pset_SlabCommon - LoadBearing: no
Component Properties - Component 1, Carbono Incorporado: 719.44 (kgCO₂); Component 1, Energia Incorporada: 4975.57 MJ; Component 1, Tipo de Componente: Nenhum
BaseQuantities - Width: 122.313 mm; Perimeter: 25430.2 mm; GrossArea: 30.5398 m2; NetArea: 30.5398 m2; GrossVolume: 3.73541 m3; NetVolume: 3.73541 m3
Component Quantities - Component 1, Massa: 6723.74 kg; Component 1, Área de Componente Projetada (Líquida): 30.5398 m2; Component 1, Área de Componente Projetada (Bruta): 30.5398 m2; Component 1, Espessura do Componente: 122.313 mm; Component 1, Volume Componente (Líquido): 3.73541 m3; Component 1, Volume do componente (Bruto): 3.73541 m3

# IfcSlab: Concreto 128, Laje-036
In: Pavimento Térreo
Type - PredefinedType: FLOOR
Classification: Laje (Classificação ARCHICAD); Material: Concreto 128.439 mm
AC_Pset_RenovationAndPhasing - Renovation Status: Existing
Pset_SlabCommon - LoadBearing: no
Component Properties - Component 1, Carbono Incorporado: 60.1284 (kgCO₂); Component 1, Energia Incorporada: 415.841 MJ; Component 1, Tipo de Componente: Nenhum
BaseQuantities - Width: 128.439 mm; Perimeter: 8389.85 mm; GrossArea: 2.43068 m2; NetArea: 2.43068 m2; GrossVolume: 0.312193 m3; NetVolume: 0.312193 m3
Component Quantities - Component 1, Massa: 561.948 kg; Component 1, Área de Componente Projetada (Líquida): 2.43068 m2; Component 1, Área de Componente Projetada (Bruta): 2.43068 m2; Component 1, Espessura do Componente: 128.439 mm; Component 1, Volume Componente (Líquido): 0.312193 m3; Component 1, Volume do componente (Bruto): 0.312193 m3

# IfcSlab: Concreto 145, Laje-038
In: Pavimento Térreo
Type - PredefinedType: FLOOR
Classification: Laje (Classificação ARCHICAD); Material: Concreto 145.029 mm
AC_Pset_RenovationAndPhasing - Renovation Status: Existing
Pset_SlabCommon - LoadBearing: no
Component Properties - Component 1, Carbono Incorporado: 20.1115 (kgCO₂); Component 1, Energia Incorporada: 139.089 MJ; Component 1, Tipo de Componente: Nenhum
BaseQuantities - Width: 145.029 mm; Perimeter: 4100 mm; GrossArea: 0.72 m2; NetArea: 0.72 m2; GrossVolume: 0.104421 m3; NetVolume: 0.104421 m3
Component Quantities - Component 1, Massa: 187.958 kg; Component 1, Área de Componente Projetada (Líquida): 0.72 m2; Component 1, Área de Componente Projetada (Bruta): 0.72 m2; Component 1, Espessura do Componente: 145.029 mm; Component 1, Volume Componente (Líquido): 0.104421 m3; Component 1, Volume do componente (Bruto): 0.104421 m3

# IfcSlab: Concreto 173 (2)
In: Pavimento Térreo
Type - PredefinedType: FLOOR
Classification: Laje (Classificação ARCHICAD); Material: Concreto 172.628 mm
AC_Pset_RenovationAndPhasing - Renovation Status: Existing
Pset_SlabCommon - LoadBearing: no
Component Properties - Component 1, Tipo de Componente: Nenhum
BaseQuantities - Width: 172.628 mm
Component Quantities - Component 1, Espessura do Componente: 172.628 mm
Name | Component 1, Carbono Incorporado | Component 1, Energia Incorporada (MJ) | Perimeter (mm) | GrossArea (m2) = NetArea (m2) | GrossVolume (m3) = NetVolume (m3) = Component 1, Volume Componente (Líquido) (m3) = Component 1, Volume do componente (Bruto) (m3) | Component 1, Massa (kg) | Component 1, Área de Componente Projetada (Líquida) (m2) = Component 1, Área de Componente Projetada (Bruta) (m2)
Laje-037 | 14.6101 (kgCO₂) | 101.042 | 3150.03 | 0.439426 | 0.0758573 | 136.543 | 0.439426
Laje-037 | 14.4534 (kgCO₂) | 99.9583 | 3124 | 0.434711 | 0.0750437 | 135.079 | 0.434724

# IfcSlab: Concreto 177, Laje-036
In: Pavimento Térreo
Type - PredefinedType: FLOOR
Classification: Laje (Classificação ARCHICAD); Material: Concreto 177.195 mm
AC_Pset_RenovationAndPhasing - Renovation Status: Existing
Pset_SlabCommon - LoadBearing: no
Component Properties - Component 1, Carbono Incorporado: 463.3 (kgCO₂); Component 1, Energia Incorporada: 3204.13 MJ; Component 1, Tipo de Componente: Nenhum
BaseQuantities - Width: 177.195 mm; Perimeter: 27475 mm; GrossArea: 13.5755 m2; NetArea: 13.5755 m2; GrossVolume: 2.4055 m3; NetVolume: 2.4055 m3
Component Quantities - Component 1, Massa: 4329.9 kg; Component 1, Área de Componente Projetada (Líquida): 13.5755 m2; Component 1, Área de Componente Projetada (Bruta): 13.5755 m2; Component 1, Espessura do Componente: 177.195 mm; Component 1, Volume Componente (Líquido): 2.4055 m3; Component 1, Volume do componente (Bruto): 2.4055 m3

# IfcSlab: Concreto 256, Laje-036
In: Pavimento Térreo
Type - PredefinedType: FLOOR
Classification: Laje (Classificação ARCHICAD); Material: Concreto 256.095 mm
AC_Pset_RenovationAndPhasing - Renovation Status: Existing
Pset_SlabCommon - LoadBearing: no
Component Properties - Component 1, Carbono Incorporado: 173.241 (kgCO₂); Component 1, Energia Incorporada: 1198.12 MJ; Component 1, Tipo de Componente: Nenhum
BaseQuantities - Width: 256.095 mm; Perimeter: 10948.7 mm; GrossArea: 3.51232 m2; NetArea: 3.51232 m2; GrossVolume: 0.899487 m3; NetVolume: 0.899487 m3
Component Quantities - Component 1, Massa: 1619.08 kg; Component 1, Área de Componente Projetada (Líquida): 3.51232 m2; Component 1, Área de Componente Projetada (Bruta): 3.51232 m2; Component 1, Espessura do Componente: 256.095 mm; Component 1, Volume Componente (Líquido): 0.899487 m3; Component 1, Volume do componente (Bruto): 0.899487 m3

# IfcSlab: Concreto 346 (2)
In: Pavimento Térreo
Type - PredefinedType: FLOOR
Classification: Laje (Classificação ARCHICAD); Material: Concreto 345.928 mm
AC_Pset_RenovationAndPhasing - Renovation Status: Existing
Pset_SlabCommon - LoadBearing: no
Component Properties - Component 1, Tipo de Componente: Nenhum
BaseQuantities - Width: 345.928 mm
Component Quantities - Component 1, Espessura do Componente: 345.928 mm
Name | Component 1, Carbono Incorporado | Component 1, Energia Incorporada (MJ) | Perimeter (mm) | GrossArea (m2) = NetArea (m2) = Component 1, Área de Componente Projetada (Líquida) (m2) = Component 1, Área de Componente Projetada (Bruta) (m2) | GrossVolume (m3) = NetVolume (m3) = Component 1, Volume Componente (Líquido) (m3) = Component 1, Volume do componente (Bruto) (m3) | Component 1, Massa (kg)
Laje-037 | 38.1844 (kgCO₂) | 264.079 | 3389.42 | 0.573118 | 0.198257 | 356.863
Laje-037 | 37.664 (kgCO₂) | 260.48 | 3360.42 | 0.565307 | 0.195555 | 352

# IfcSlab: Concreto 9, Laje-032
In: Pavimento Térreo
Type - PredefinedType: FLOOR
Classification: Laje (Classificação ARCHICAD); Material: Concreto 9 mm
AC_Pset_RenovationAndPhasing - Renovation Status: Existing
Pset_SlabCommon - LoadBearing: no
Component Properties - Component 1, Carbono Incorporado: 2.4961 (kgCO₂); Component 1, Energia Incorporada: 17.2627 MJ; Component 1, Tipo de Componente: Nenhum
BaseQuantities - Width: 9 mm; Perimeter: 4800 mm; GrossArea: 1.44 m2; NetArea: 1.44 m2; GrossVolume: 0.01296 m3; NetVolume: 0.01296 m3
Component Quantities - Component 1, Massa: 23.328 kg; Component 1, Área de Componente Projetada (Líquida): 1.44 m2; Component 1, Área de Componente Projetada (Bruta): 1.44 m2; Component 1, Espessura do Componente: 9 mm; Component 1, Volume Componente (Líquido): 0.01296 m3; Component 1, Volume do componente (Bruto): 0.01296 m3

# IfcSlab: IfcSlab, Patamar - 003
In: Pavimento Térreo
Type - PredefinedType: LANDING
Classification: Patamar de Escada (Classificação ARCHICAD); Material: Concreto - Estrutural
AC_Pset_RenovationAndPhasing - Renovation Status: Existing
Component Properties - Component 1, Carbono Incorporado: 187.329 (kgCO₂); Component 1, Energia Incorporada: 1816.53 MJ
BaseQuantities - GrossVolume: 0.411351 m3; NetVolume: 0.411351 m3
Component Quantities - Component 1, Massa: 946.107 kg; Component 1, Volume Componente (Líquido): 0.411351 m3; Component 1, Volume do componente (Bruto): 0.411351 m3

# IfcStair (6)
In: Pavimento Térreo
Classification: Escada (Classificação ARCHICAD)
Pset_StairCommon - RequiredHeadroom: 2200 mm
AC_Pset_RenovationAndPhasing - Renovation Status: Existing
Name | NumberOfRiser | NumberOfTreads | RiserHeight (mm) | Length (mm) | Height (mm) | GrossVolume (m3) = NetVolume (m3)
Escada - 012 | 13 | 12 | 175.385 | 3360 | 2280 | 1.48264
Escada - 004 | 2 | 1 | 130 | 320 | 260 | 0.0924223
Escada - 012 | 13 | 12 | 175.385 | 3360 | 2280 | 1.46799
Escada - 009 | 13 | 12 | 165.385 | 3600 | 2150 | 1.67652
Escada - 001 | 9 | 8 | 165.556 | 2480 | 1490 | 0.825991
Escada - 008 | 9 | 8 | 166.667 | 4171.75 | 1500 | 1.59033

# IfcWall: Bloco de Concreto - Estrutural (5)
In: Pavimento Térreo
Classification: Parede (Classificação ARCHICAD); Material: Bloco de Concreto - Estrutural
AC_Pset_RenovationAndPhasing - Renovation Status: Existing
Pset_WallCommon - LoadBearing: yes
Component Properties - Component 1, Tipo de Componente: Nenhum
Name | Component 1, Carbono Incorporado | Component 1, Energia Incorporada (MJ) | Component 1, Massa (kg) | Component 1, Volume Componente (Líquido) (m3) = Component 1, Volume do componente (Bruto) (m3)
Parede-088 | 104.088 (kgCO₂) | 851.631 | 1182.82 | 0.844872
Parede-086 | 35.4686 (kgCO₂) | 290.198 | 403.052 | 0.287894
Parede-088 | 12.6324 (kgCO₂) | 103.356 | 143.55 | 0.102536
Parede-087 | 1356.27 (kgCO₂) | 11096.8 | 15412.2 | 11.0087
Parede-090 | 20.8859 (kgCO₂) | 170.884 | 237.339 | 0.169528

# IfcWall: Ferro, Parede-083
In: Pavimento Térreo
Classification: Parede (Classificação ARCHICAD); Material: Ferro
AC_Pset_RenovationAndPhasing - Renovation Status: Existing
Pset_WallCommon - LoadBearing: yes
Component Properties - Component 1, Carbono Incorporado: 1.82099 (kgCO₂); Component 1, Energia Incorporada: 37.6238 MJ; Component 1, Tipo de Componente: Nenhum
Component Quantities - Component 1, Massa: 1.50495 kg; Component 1, Volume Componente (Líquido): 0.00020066 m3; Component 1, Volume do componente (Bruto): 0.00020066 m3

# IfcWall: Floreira skate 400 x 450 (4)
In: Pavimento Térreo
Classification: Parede (Classificação ARCHICAD); Material: Concreto Armado - Estrutural
AC_Pset_RenovationAndPhasing - Renovation Status: Existing
Pset_WallCommon - LoadBearing: yes
Component Properties - Component 1, Tipo de Componente: Núcleo
BaseQuantities - Height: 450 mm; Width: 400 mm
Component Quantities - Component 1, Área de Seção Transversal do Componente: 0.11 m2
Name | Component 1, Carbono Incorporado | Component 1, Energia Incorporada (MJ) | Length (mm) | GrossFootprintArea (m2) = NetFootprintArea (m2) | GrossSideArea (m2) = NetSideArea (m2) | GrossVolume (m3) = NetVolume (m3) = Component 1, Volume Componente (Líquido) (m3) = Component 1, Volume do componente (Bruto) (m3) | Component 1, Massa (kg)
Parede-096 | 84.7968 (kgCO₂) | 816.432 | 1600 | 0.52 | 0.61 | 0.146 | 350.4
Parede-093 | 78.1403 (kgCO₂) | 752.343 | 950.355 | 0.540142 | 0.53766 | 0.134539 | 322.894
Parede-095 | 60.7163 (kgCO₂) | 584.583 | 950.355 | 0.400142 | 0.42766 | 0.104539 | 250.894
Parede-094 | 102.221 (kgCO₂) | 984.192 | 1600 | 0.66 | 0.72 | 0.176 | 422.4

# IfcWall: Perfil Skate 32 x 17, Parede-083
In: Pavimento Térreo
Classification: Parede (Classificação ARCHICAD); Material: Ferro
AC_Pset_RenovationAndPhasing - Renovation Status: Existing
Pset_WallCommon - LoadBearing: yes
Component Properties - Component 1, Carbono Incorporado: 2.15124 (kgCO₂); Component 1, Energia Incorporada: 44.447 MJ; Component 1, Tipo de Componente: Núcleo
BaseQuantities - Length: 5850.17 mm; Height: 17.378 mm; Width: 32.2976 mm; GrossFootprintArea: 0.117003 m2; NetFootprintArea: 0.117003 m2; GrossSideArea: 0.124376 m2; NetSideArea: 0.124376 m2; GrossVolume: 0.000237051 m3; NetVolume: 0.000237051 m3
Component Quantities - Component 1, Massa: 1.77788 kg; Component 1, Área de Seção Transversal do Componente: 0.0000405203 m2; Component 1, Volume Componente (Líquido): 0.000237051 m3; Component 1, Volume do componente (Bruto): 0.000237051 m3

# IfcWall: Rampa Nova 01 13400 x 1000, Parede-092
In: Pavimento Térreo
Classification: Parede (Classificação ARCHICAD); Material: Concreto - Contra Piso
AC_Pset_RenovationAndPhasing - Renovation Status: Existing
Pset_WallCommon - LoadBearing: yes
Component Properties - Component 1, Carbono Incorporado: 4804.01 (kgCO₂); Component 1, Energia Incorporada: 33224 MJ; Component 1, Tipo de Componente: Núcleo
BaseQuantities - Length: 5850 mm; Height: 1000 mm; Width: 13400 mm; GrossFootprintArea: 78.39 m2; NetFootprintArea: 78.39 m2; GrossSideArea: 18.0997 m2; NetSideArea: 18.0997 m2; GrossVolume: 24.9429 m3; NetVolume: 24.9429 m3
Component Quantities - Component 1, Massa: 44897.3 kg; Component 1, Área de Seção Transversal do Componente: 4.26097 m2; Component 1, Volume Componente (Líquido): 24.9429 m3; Component 1, Volume do componente (Bruto): 24.9429 m3

# IfcWallStandardCase: Bloco de Concreto - Estrutural 120 (115)
In: Pavimento Térreo
Classification: Parede (Classificação ARCHICAD); Material: Bloco de Concreto - Estrutural 120 mm
AC_Pset_RenovationAndPhasing - Renovation Status: Existing
Pset_WallCommon - LoadBearing: yes
Component Properties - Component 1, Tipo de Componente: Nenhum
BaseQuantities - Width: 120 mm
Component Quantities - Component 1, Espessura do Componente: 120 mm; Component 1, Largura do Componente Retangular: 120 mm
Name | Component 1, Carbono Incorporado | Component 1, Energia Incorporada (MJ) | Length (mm) | Height (mm) = Component 1, Altura do Componente Retangular (mm) | GrossFootprintArea (m2) = NetFootprintArea (m2) | GrossSideArea (m2) = NetSideArea (m2) | GrossVolume (m3) = NetVolume (m3) = Component 1, Volume Componente (Líquido) (m3) = Component 1, Volume do componente (Bruto) (m3) | Component 1, Massa (kg) | Component 1, Área de Componente Projetada (Líquida) (m2) = Component 1, Área de Componente Projetada (Bruta) (m2) | Component 1, Área de Seção Transversal do Componente (m2)
Parede-083 | 5.50951 (kgCO₂) | 45.0778 | 702.961 | 569.244 | 0.0843596 | 0.372667 | 0.04472 | 62.6081 | 0.372687 | 0.0683093
2 x Parede-081 | 19.9396 (kgCO₂) | 163.142 | 888.328 | 1345.09 | 0.121921 | 1.34873 | 0.161847 | 226.586 | 1.39085 | 0.16141
Parede-087 | 20.4742 (kgCO₂) | 167.516 | 3953.2 | 340 | 0.488784 | 1.38489 | 0.166187 | 232.661 | 1.38489 | 0.0408
Parede-086 | 20.5046 (kgCO₂) | 167.765 | 2630 | 504.344 | 0.33 | 1.38694 | 0.166433 | 233.007 | 1.38694 | 0.0605212
Parede-085 | 12.395 (kgCO₂) | 101.413 | 700.272 | 1197.27 | 0.084031 | 0.838403 | 0.100608 | 140.852 | 0.838415 | 0.143673
Parede-088 | 70.5578 (kgCO₂) | 577.291 | 9634.61 | 495.358 | 1.15615 | 4.77258 | 0.572709 | 801.793 | 4.77258 | 0.0594429
Parede-088 | 60.4178 (kgCO₂) | 494.327 | 8250 | 495.358 | 0.99 | 4.0867 | 0.490404 | 686.566 | 4.0867 | 0.0594429
Parede-082 | 12.8821 (kgCO₂) | 105.399 | 1089.41 | 799.844 | 0.130729 | 0.871355 | 0.104563 | 146.388 | 0.871355 | 0.0959812
Parede-084 | 11.3056 (kgCO₂) | 92.5003 | 3840.43 | 196.987 | 0.468051 | 0.764718 | 0.0917662 | 128.473 | 0.764746 | 0.0236384
Parede-084 | 21.3162 (kgCO₂) | 174.406 | 4143.53 | 358.52 | 0.482599 | 1.44185 | 0.173021 | 242.23 | 1.44947 | 0.0430224
3 x Parede-085 | 12.3903 (kgCO₂) | 101.376 | 640 | 1197.27 | 0.084 | 0.838091 | 0.100571 | 140.799 | 0.838091 | 0.143673
Parede-089 | 11.9847 (kgCO₂) | 98.0567 | 2469.13 | 340 | 0.286113 | 0.810654 | 0.0972784 | 136.19 | 0.831054 | 0.0408
Parede-087 | 5.49253 (kgCO₂) | 44.9389 | 750 | 495.358 | 0.09 | 0.371518 | 0.0445822 | 62.4151 | 0.371518 | 0.0594429
Parede-082 | 44.0085 (kgCO₂) | 360.07 | 4080 | 718.997 | 0.504 | 2.97677 | 0.357212 | 500.097 | 2.97677 | 0.0862797
Parede-081 | 25.1685 (kgCO₂) | 205.924 | 2256.18 | 798.824 | 0.269523 | 1.70242 | 0.20429 | 286.006 | 1.73146 | 0.0958589
Parede-082 | 62.8582 (kgCO₂) | 514.294 | 7095.77 | 599.284 | 0.851376 | 4.25177 | 0.510213 | 714.298 | 4.25835 | 0.0719141
2 x Parede-081 | 15.295 (kgCO₂) | 125.141 | 883.637 | 1345.09 | 0.105115 | 1.03456 | 0.124147 | 173.806 | 1.07669 | 0.16141
Parede-082 | 50.6107 (kgCO₂) | 414.087 | 4696.89 | 737.981 | 0.562462 | 3.42334 | 0.410801 | 575.121 | 3.42687 | 0.0885578
Parede-082 | 61.5736 (kgCO₂) | 503.784 | 7701.52 | 540.786 | 0.924183 | 4.16488 | 0.499786 | 699.7 | 4.16488 | 0.0648944
Parede-081 | 84.2069 (kgCO₂) | 688.965 | 4916.17 | 1130.98 | 0.60434 | 5.69581 | 0.683497 | 956.896 | 5.69581 | 0.135718
Parede-085 | 3.27719 (kgCO₂) | 26.8133 | 699.102 | 345.685 | 0.0839122 | 0.221671 | 0.0266005 | 37.2408 | 0.221705 | 0.0414823
Parede-083 | 1.90659 (kgCO₂) | 15.5994 | 712.702 | 166.899 | 0.0927243 | 0.128963 | 0.0154756 | 21.6658 | 0.128963 | 0.0200279
Parede-087 | 88.3576 (kgCO₂) | 722.925 | 3134.22 | 1928.35 | 0.376108 | 5.97657 | 0.717188 | 1004.06 | 5.97656 | 0.231402
Parede-088 | 12.8568 (kgCO₂) | 105.192 | 1402.48 | 562.03 | 0.185679 | 0.869644 | 0.104357 | 146.1 | 0.903363 | 0.0674436
Parede-081 | 5.61051 (kgCO₂) | 45.9042 | 971.321 | 340 | 0.133941 | 0.379499 | 0.0455399 | 63.7558 | 0.399899 | 0.0408
Parede-081 | 21.2616 (kgCO₂) | 173.959 | 999.029 | 1345.09 | 0.128303 | 1.43815 | 0.172578 | 241.609 | 1.48706 | 0.16141
Parede-084 | 29.9556 (kgCO₂) | 245.091 | 3564.75 | 560.93 | 0.44217 | 2.02622 | 0.243146 | 340.404 | 2.02622 | 0.0673115
Parede-084 | 2.53955 (kgCO₂) | 20.7781 | 1118.08 | 166.899 | 0.123507 | 0.171777 | 0.0206132 | 28.8585 | 0.182742 | 0.0200279
Parede-084 | 27.2073 (kgCO₂) | 222.605 | 3220.84 | 560.93 | 0.393701 | 1.84032 | 0.220839 | 309.174 | 1.84032 | 0.0673115
Parede-088 | 11.2383 (kgCO₂) | 91.9499 | 1534.58 | 495.358 | 0.18415 | 0.760168 | 0.0912201 | 127.708 | 0.760168 | 0.0594429
Parede-083 | 67.0705 (kgCO₂) | 548.759 | 2704.8 | 1677.27 | 0.324577 | 4.5367 | 0.544404 | 762.165 | 4.5367 | 0.201273
Parede-082 | 17.3578 (kgCO₂) | 142.018 | 700 | 1677.27 | 0.084 | 1.17409 | 0.140891 | 197.247 | 1.17409 | 0.201273
Parede-081 | 52.9877 (kgCO₂) | 433.536 | 5885.88 | 596.673 | 0.720822 | 3.58412 | 0.430095 | 602.133 | 3.59059 | 0.0716008
Parede-082 | 13.6851 (kgCO₂) | 111.969 | 1565.33 | 570.244 | 0.194794 | 0.925669 | 0.11108 | 155.512 | 0.92571 | 0.0684293
Parede-085 | 2.0324 (kgCO₂) | 16.6287 | 712.702 | 210.621 | 0.0783243 | 0.137473 | 0.0164968 | 23.0955 | 0.137473 | 0.0252746
Parede-082 | 15.5698 (kgCO₂) | 127.39 | 1912.53 | 540.786 | 0.243904 | 1.05315 | 0.126379 | 176.93 | 1.05315 | 0.0648944
Parede-081 | 11.9086 (kgCO₂) | 97.4337 | 715.704 | 1345.09 | 0.0846655 | 0.805504 | 0.0966604 | 135.325 | 0.854415 | 0.16141
Parede-087 | 54.594 (kgCO₂) | 446.678 | 3265.11 | 1130.98 | 0.391813 | 3.69278 | 0.443133 | 620.386 | 3.69278 | 0.135718
Parede-082 | 14.3822 (kgCO₂) | 117.672 | 700 | 1677.27 | 0.0696 | 0.972819 | 0.116738 | 163.434 | 0.972819 | 0.201273
Parede-088 | 35.1522 (kgCO₂) | 287.609 | 4800 | 495.358 | 0.576 | 2.37772 | 0.285326 | 399.456 | 2.37772 | 0.0594429
Parede-083 | 65.1056 (kgCO₂) | 532.682 | 5758.97 | 764.684 | 0.691076 | 4.40379 | 0.528455 | 739.837 | 4.40379 | 0.091762
Parede-081 | 22.8882 (kgCO₂) | 187.267 | 1964.6 | 764.684 | 0.242952 | 1.54818 | 0.185781 | 260.093 | 1.54818 | 0.091762
Parede-084 | 16.1231 (kgCO₂) | 131.916 | 3496.8 | 307.068 | 0.434017 | 1.09058 | 0.130869 | 183.217 | 1.09058 | 0.0368482
Parede-085 | 13.9865 (kgCO₂) | 114.435 | 670.307 | 1197.27 | 0.0948369 | 0.946057 | 0.113527 | 158.938 | 0.946057 | 0.143673
Parede-081 | 36.8717 (kgCO₂) | 301.678 | 1854.18 | 1345.09 | 0.222501 | 2.49403 | 0.299284 | 418.997 | 2.49403 | 0.16141
Parede-088 | 4.74874 (kgCO₂) | 38.8533 | 835.024 | 340 | 0.113368 | 0.321208 | 0.038545 | 53.963 | 0.341608 | 0.0408
Parede-081 | 5.02858 (kgCO₂) | 41.1429 | 827.789 | 358.52 | 0.113847 | 0.340136 | 0.0408164 | 57.1429 | 0.343947 | 0.0430224
2 x Parede-085 | 10.2686 (kgCO₂) | 84.0159 | 700 | 1197.27 | 0.084 | 0.694576 | 0.0833491 | 116.689 | 0.694576 | 0.143673
Parede-084 | 25.5439 (kgCO₂) | 208.996 | 3020.26 | 560.93 | 0.369631 | 1.72781 | 0.207337 | 290.272 | 1.72781 | 0.0673115
Parede-082 | 16.4878 (kgCO₂) | 134.9 | 1900.05 | 586.956 | 0.228006 | 1.11525 | 0.133829 | 187.361 | 1.11529 | 0.0704347
Parede-082 | 16.8111 (kgCO₂) | 137.545 | 1481.98 | 709.431 | 0.192351 | 1.13711 | 0.136454 | 191.035 | 1.14478 | 0.0851317
Parede-081 | 44.6638 (kgCO₂) | 365.431 | 2256.18 | 1345.09 | 0.269523 | 3.02109 | 0.362531 | 507.544 | 3.07 | 0.16141
Parede-083 | 131.787 (kgCO₂) | 1078.26 | 10928.8 | 815.66 | 1.31146 | 8.91419 | 1.0697 | 1497.58 | 8.91419 | 0.0978792
Parede-082 | 44.5718 (kgCO₂) | 364.679 | 7798.56 | 386.593 | 0.935827 | 3.01487 | 0.361784 | 506.498 | 3.01487 | 0.0463912
Parede-100 | 31.8584 (kgCO₂) | 260.66 | 1284.78 | 1677.27 | 0.154173 | 2.15492 | 0.258591 | 362.027 | 2.15492 | 0.201273
Parede-099 | 17.4195 (kgCO₂) | 142.524 | 702.491 | 1677.27 | 0.084299 | 1.17827 | 0.141392 | 197.949 | 1.17832 | 0.201273
Parede-098 | 121.953 (kgCO₂) | 997.794 | 4918.08 | 1677.27 | 0.590169 | 8.24896 | 0.989875 | 1385.83 | 8.24906 | 0.201273
Parede-097 | 17.8124 (kgCO₂) | 145.738 | 718.335 | 1677.27 | 0.0862002 | 1.20484 | 0.144581 | 202.414 | 1.2049 | 0.201273
Parede-096 | 77.614 (kgCO₂) | 635.024 | 3130 | 1677.27 | 0.3756 | 5.24987 | 0.629984 | 881.977 | 5.24987 | 0.201273
Parede-095 | 79.2626 (kgCO₂) | 648.512 | 3206.64 | 1677.27 | 0.383578 | 5.36138 | 0.643365 | 900.711 | 5.42237 | 0.201273
Parede-094 | 60.492 (kgCO₂) | 494.934 | 2419.05 | 1677.27 | 0.302761 | 4.09172 | 0.491006 | 687.409 | 4.2017 | 0.201273
Parede-093 | 12.2427 (kgCO₂) | 100.167 | 604.492 | 1347.27 | 0.0737581 | 0.828103 | 0.0993723 | 139.121 | 0.877094 | 0.161673
Parede-092 | 80.2514 (kgCO₂) | 656.602 | 3259.97 | 1677.27 | 0.391196 | 5.42826 | 0.651391 | 911.947 | 5.42826 | 0.201273
Parede-091 | 12.6341 (kgCO₂) | 103.37 | 519.664 | 1677.27 | 0.0611406 | 0.85458 | 0.10255 | 143.569 | 0.915571 | 0.201273
Parede-090 | 97.3465 (kgCO₂) | 796.471 | 3923.31 | 1677.27 | 0.471092 | 6.58458 | 0.79015 | 1106.21 | 6.69818 | 0.201273
Parede-089 | 97.3248 (kgCO₂) | 796.293 | 3927.32 | 1677.27 | 0.470987 | 6.58311 | 0.789974 | 1105.96 | 6.69663 | 0.201273
Parede-088 | 13.1367 (kgCO₂) | 107.482 | 519.64 | 1677.27 | 0.0635728 | 0.888574 | 0.106629 | 149.28 | 0.949481 | 0.201273
Parede-087 | 9.98905 (kgCO₂) | 81.7286 | 1443.19 | 488.483 | 0.165983 | 0.675666 | 0.08108 | 113.512 | 0.675666 | 0.0586179
Parede-086 | 19.4986 (kgCO₂) | 159.534 | 2639.99 | 488.483 | 0.323998 | 1.3189 | 0.158268 | 221.575 | 1.3189 | 0.0586179
2 x Parede-082 | 8.34229 (kgCO₂) | 68.2551 | 1778.97 | 340 | 0.227876 | 0.564278 | 0.0677134 | 94.7987 | 0.564278 | 0.0408
Parede-083 | 4.14599 (kgCO₂) | 33.9217 | 1591.43 | 166.899 | 0.201634 | 0.280437 | 0.0336525 | 47.1135 | 0.291375 | 0.0200279
Parede-081 | 61.8633 (kgCO₂) | 506.154 | 2371.85 | 1677.27 | 0.300241 | 4.18448 | 0.502137 | 702.992 | 4.23339 | 0.201273
Parede-085 | 47.6934 (kgCO₂) | 390.218 | 1923.37 | 1677.27 | 0.230804 | 3.22601 | 0.387121 | 541.97 | 3.34799 | 0.201273
Parede-084 | 4.07898 (kgCO₂) | 33.3735 | 749.823 | 340.698 | 0.0971787 | 0.275905 | 0.0331086 | 46.3521 | 0.275916 | 0.0408838
Parede-088 | 25.0417 (kgCO₂) | 204.887 | 3133.55 | 562.03 | 0.376027 | 1.69384 | 0.203261 | 284.565 | 1.69384 | 0.0674436
Parede-081 | 13.3167 (kgCO₂) | 108.955 | 671.255 | 1345.09 | 0.0889697 | 0.900752 | 0.10809 | 151.326 | 0.9298 | 0.16141
Parede-081 | 58.9956 (kgCO₂) | 482.691 | 2256.2 | 1677.27 | 0.286364 | 3.9905 | 0.47886 | 670.405 | 4.03942 | 0.201273
Parede-081 | 9.83152 (kgCO₂) | 80.4397 | 611.255 | 1345.09 | 0.0721316 | 0.665011 | 0.0798013 | 111.722 | 0.713922 | 0.16141
Parede-085 | 10.2336 (kgCO₂) | 83.7291 | 638.02 | 1197.27 | 0.0837623 | 0.692204 | 0.0830645 | 116.29 | 0.692204 | 0.143673
Parede-082 | 6.25827 (kgCO₂) | 51.2041 | 971.695 | 435.645 | 0.116603 | 0.423314 | 0.0507977 | 71.1168 | 0.423314 | 0.0522774
Parede-087 | 9.54395 (kgCO₂) | 78.0869 | 1280 | 504.344 | 0.1536 | 0.64556 | 0.0774672 | 108.454 | 0.64556 | 0.0605212
Parede-088 | 19.6098 (kgCO₂) | 160.444 | 2630 | 504.344 | 0.3156 | 1.32642 | 0.159171 | 222.839 | 1.32642 | 0.0605212
Parede-088 | 7.30997 (kgCO₂) | 59.8088 | 1186.48 | 501.23 | 0.118377 | 0.494451 | 0.0593342 | 83.0678 | 0.494474 | 0.0601476
Parede-081 | 16.3859 (kgCO₂) | 134.066 | 1959.69 | 548.772 | 0.242363 | 1.10835 | 0.133002 | 186.203 | 1.10835 | 0.0658526
Parede-085 | 10.2686 (kgCO₂) | 84.0159 | 640 | 1197.27 | 0.084 | 0.694576 | 0.0833491 | 116.689 | 0.694576 | 0.143673
Parede-086 | 13.9192 (kgCO₂) | 113.884 | 610.572 | 1677.27 | 0.0720496 | 0.941502 | 0.11298 | 158.172 | 1.00249 | 0.201273
Parede-090 | 32.64 (kgCO₂) | 267.055 | 4404.75 | 501.23 | 0.52857 | 2.2078 | 0.264935 | 370.91 | 2.2078 | 0.0601476
Parede-086 | 8.64921 (kgCO₂) | 70.7662 | 1280 | 504.344 | 0.1392 | 0.585038 | 0.0702046 | 98.2865 | 0.585038 | 0.0605212
Parede-084 | 73.0912 (kgCO₂) | 598.019 | 2937.45 | 1677.27 | 0.353713 | 4.94394 | 0.593273 | 830.582 | 5.00493 | 0.201273
Parede-082 | 35.2866 (kgCO₂) | 288.708 | 3149.04 | 787.975 | 0.363485 | 2.38681 | 0.286417 | 400.984 | 2.38682 | 0.094557
Parede-086 | 43.3882 (kgCO₂) | 354.995 | 6026.08 | 487.018 | 0.72313 | 2.93481 | 0.352177 | 493.048 | 2.93481 | 0.0584421
Parede-083 | 49.1318 (kgCO₂) | 401.988 | 6175.91 | 548.772 | 0.726709 | 3.32331 | 0.398797 | 558.316 | 3.32331 | 0.0658526
Parede-081 | 29.2363 (kgCO₂) | 239.206 | 6162.65 | 320.846 | 0.73963 | 1.97756 | 0.237308 | 332.231 | 1.98098 | 0.0385016
Parede-081 | 40.0736 (kgCO₂) | 327.875 | 1955.19 | 1345.09 | 0.241823 | 2.71061 | 0.325273 | 455.382 | 2.71061 | 0.16141
Parede-083 | 72.0977 (kgCO₂) | 589.89 | 3953.2 | 1197.27 | 0.488784 | 4.87674 | 0.585208 | 819.292 | 4.87674 | 0.143673
Parede-081 | 31.408 (kgCO₂) | 256.975 | 3475.03 | 625.744 | 0.418394 | 2.12446 | 0.254935 | 356.909 | 2.12921 | 0.0750892
Parede-084 | 24.2002 (kgCO₂) | 198.002 | 3619.74 | 448.642 | 0.448772 | 1.63692 | 0.196431 | 275.003 | 1.63694 | 0.053837
Parede-081 | 72.1629 (kgCO₂) | 590.424 | 11294.6 | 432.132 | 1.35546 | 4.88115 | 0.585738 | 820.033 | 4.88583 | 0.0518559
Parede-088 | 24.3584 (kgCO₂) | 199.296 | 3057.91 | 562.03 | 0.35975 | 1.64762 | 0.197714 | 276.8 | 1.70174 | 0.0674436
Parede-083 | 116.724 (kgCO₂) | 955.017 | 10866.3 | 726.475 | 1.31721 | 7.89531 | 0.947437 | 1326.41 | 7.90305 | 0.087177
Parede-086 | 5.49253 (kgCO₂) | 44.9389 | 750 | 495.358 | 0.09 | 0.371518 | 0.0445822 | 62.4151 | 0.371518 | 0.0594429
Parede-088 | 45.2922 (kgCO₂) | 370.572 | 6184.61 | 495.358 | 0.742153 | 3.06359 | 0.367631 | 514.684 | 3.06359 | 0.0594429
Parede-087 | 3.55257 (kgCO₂) | 29.0665 | 365.101 | 495.358 | 0.0582121 | 0.240298 | 0.0288358 | 40.3701 | 0.240298 | 0.0594429
Parede-086 | 26.6391 (kgCO₂) | 217.956 | 1625 | 1197.27 | 0.1806 | 1.80189 | 0.216227 | 302.717 | 1.8019 | 0.143673
Parede-083 | 16.5488 (kgCO₂) | 135.399 | 1550.59 | 718.997 | 0.187458 | 1.11937 | 0.134325 | 188.055 | 1.12318 | 0.0862797
Parede-087 | 6.70356 (kgCO₂) | 54.8473 | 1453.62 | 340 | 0.160035 | 0.453434 | 0.054412 | 76.1768 | 0.453437 | 0.0408
Parede-086 | 1.79496 (kgCO₂) | 14.6861 | 365.101 | 495.358 | 0.0294121 | 0.121413 | 0.0145695 | 20.3973 | 0.121413 | 0.0594429
Parede-084 | 25.7891 (kgCO₂) | 211.002 | 5130.57 | 340 | 0.615668 | 1.74439 | 0.209327 | 293.058 | 1.74439 | 0.0408
Parede-082 | 13.6743 (kgCO₂) | 111.881 | 1625.3 | 570.244 | 0.194641 | 0.924938 | 0.110993 | 155.39 | 0.924959 | 0.0684293

# IfcWallStandardCase: Bloco de Concreto - Estrutural 200 (47)
In: Pavimento Térreo
Classification: Parede (Classificação ARCHICAD); Material: Bloco de Concreto - Estrutural 200 mm
AC_Pset_RenovationAndPhasing - Renovation Status: Existing
Pset_WallCommon - LoadBearing: yes
Component Properties - Component 1, Tipo de Componente: Nenhum
BaseQuantities - Width: 200 mm
Component Quantities - Component 1, Espessura do Componente: 200 mm; Component 1, Largura do Componente Retangular: 200 mm
Name | Component 1, Carbono Incorporado | Component 1, Energia Incorporada (MJ) | Length (mm) | Height (mm) | GrossFootprintArea (m2) = NetFootprintArea (m2) | GrossSideArea (m2) = NetSideArea (m2) | GrossVolume (m3) = NetVolume (m3) = Component 1, Volume Componente (Líquido) (m3) = Component 1, Volume do componente (Bruto) (m3) | Component 1, Massa (kg) | Component 1, Área de Componente Projetada (Líquida) (m2) = Component 1, Área de Componente Projetada (Bruta) (m2) | Component 1, Altura do Componente Retangular (mm) | Component 1, Área de Seção Transversal do Componente (m2)
Parede-083 | 1373.82 (kgCO₂) | 11240.3 | 17203.3 | 3332.73 | 3.48065 | 55.7555 | 11.1511 | 15611.5 | 55.7557 | 3332.73 | 0.666547
Parede-088 | 40.1963 (kgCO₂) | 328.879 | 987.319 | 1838.51 | 0.177464 | 1.63134 | 0.326268 | 456.776 | 1.63141 | 1838.51 | 0.367701
Parede-088 | 709.547 (kgCO₂) | 5805.38 | 12353.1 | 2319.48 | 2.4989 | 28.7965 | 5.75931 | 8063.03 | 28.9804 | 2319.48 | 0.463896
Parede-081 | 315.901 (kgCO₂) | 2584.64 | 5062.62 | 2532.95 | 1.01252 | 12.8207 | 2.56413 | 3589.78 | 12.8207 | 2532.95 | 0.50659
Parede-081 | 317.546 (kgCO₂) | 2598.11 | 5353.34 | 2407.36 | 1.07067 | 12.8874 | 2.57749 | 3608.48 | 12.8874 | 2407.36 | 0.481472
Parede-086 | 293.093 (kgCO₂) | 2398.03 | 4955.11 | 2450 | 0.971021 | 11.895 | 2.379 | 3330.6 | 11.895 | 2450 | 0.49
Parede-090 | 659.078 (kgCO₂) | 5392.46 | 9820.48 | 2751.75 | 1.9441 | 26.7483 | 5.34966 | 7489.52 | 26.7483 | 2751.75 | 0.550349
Parede-088 | 36.3692 (kgCO₂) | 297.567 | 1085.67 | 1838.51 | 0.160568 | 1.47602 | 0.295205 | 413.287 | 1.84369 | 1838.51 | 0.367701
Parede-081 | 242.587 (kgCO₂) | 1984.8 | 6500.67 | 1469.29 | 1.34013 | 9.84525 | 1.96905 | 2756.67 | 9.84527 | 1469.29 | 0.293859
Parede-081 | 658.312 (kgCO₂) | 5386.19 | 19239.1 | 2532.95 | 3.84783 | 26.7172 | 5.34344 | 7480.81 | 26.7173 | 2532.95 | 0.50659
Parede-081 | 95.239 (kgCO₂) | 779.228 | 3400 | 1509.99 | 0.68 | 3.86522 | 0.773044 | 1082.26 | 3.86526 | 1509.99 | 0.301999
Parede-088 | 271.48 (kgCO₂) | 2221.2 | 5894.32 | 1838.51 | 1.19857 | 10.9982 | 2.20357 | 3085 | 11.0207 | 1838.51 | 0.367701
Parede-084 | 625.634 (kgCO₂) | 5118.82 | 10933.9 | 2301.19 | 2.20677 | 25.391 | 5.07819 | 7109.47 | 25.3911 | 2301.19 | 0.460237
Parede-081 | 404.574 (kgCO₂) | 3310.15 | 20524.2 | 800 | 4.10485 | 16.4194 | 3.28388 | 4597.43 | 16.4194 | 800 | 0.16
Parede-081 | 30.3103 (kgCO₂) | 247.994 | 1667.57 | 740.149 | 0.333514 | 1.17874 | 0.246025 | 344.436 | 1.23424 | 740.149 | 0.14803
Parede-089 | 241.074 (kgCO₂) | 1972.43 | 7531.86 | 1299 | 1.50637 | 9.78386 | 1.95677 | 2739.48 | 9.78386 | 1299 | 0.259799
Parede-081 | 138.429 (kgCO₂) | 1132.6 | 3400 | 2567.68 | 0.68 | 5.61805 | 1.12361 | 1573.05 | 5.61805 | 2567.68 | 0.513535
Parede-081 | 264.238 (kgCO₂) | 2161.95 | 4947.5 | 2167.56 | 0.989504 | 10.724 | 2.14479 | 3002.71 | 10.724 | 2167.56 | 0.433512
Parede-083 | 0.177803 (kgCO₂) | 1.45475 | 20003.1 | 2297.39 | 0.000628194 | 0.00721604 | 0.00144321 | 2.02049 | 0.00721604 | 2297.39 | 0.459478
Parede-083 | 1320.38 (kgCO₂) | 10803.1 | 20000 | 2679.33 | 4.00001 | 53.849 | 10.7174 | 15004.3 | 54.1114 | 2679.33 | 0.535867
Parede-083 | 404.617 (kgCO₂) | 3310.5 | 10633.8 | 1544.24 | 2.12677 | 16.4211 | 3.28423 | 4597.92 | 16.4211 | 1544.24 | 0.308847
Parede-090 | 976.329 (kgCO₂) | 7988.14 | 14598.3 | 2751.75 | 2.8799 | 39.6237 | 7.92475 | 11094.6 | 39.6268 | 2751.75 | 0.550349
Parede-090 | 312.26 (kgCO₂) | 2554.86 | 4505.4 | 2751.75 | 0.921081 | 12.6729 | 2.53458 | 3548.41 | 12.6729 | 2751.75 | 0.550349
Parede-082 | 98.56 (kgCO₂) | 806.4 | 5100 | 800 | 1 | 4 | 0.8 | 1120 | 4 | 800 | 0.16
Parede-083 | 602.951 (kgCO₂) | 4933.24 | 10633.8 | 2301.19 | 2.12677 | 24.4704 | 4.89408 | 6851.72 | 24.4704 | 2301.19 | 0.460237
Parede-086 | 466.228 (kgCO₂) | 3814.6 | 16602.4 | 1153.59 | 3.28048 | 18.9216 | 3.78432 | 5298.05 | 18.9216 | 1153.59 | 0.230718
Parede-081 | 1163.93 (kgCO₂) | 9523.08 | 17559.7 | 2676.98 | 3.53194 | 47.2375 | 9.4475 | 13226.5 | 47.2375 | 2676.98 | 0.535396
Parede-086 | 326.383 (kgCO₂) | 2670.41 | 5017.51 | 2639.97 | 1.0035 | 13.2461 | 2.64921 | 3708.9 | 13.2461 | 2639.97 | 0.527994
Parede-088 | 303.124 (kgCO₂) | 2480.1 | 9470.46 | 1299 | 1.89409 | 12.3021 | 2.46042 | 3444.59 | 12.3021 | 1299 | 0.259799
Parede-088 | 332.148 (kgCO₂) | 2717.57 | 8000.01 | 1657.9 | 1.64 | 13.48 | 2.696 | 3774.41 | 13.48 | 1657.9 | 0.331581
Parede-088 | 238.631 (kgCO₂) | 1952.44 | 5126.29 | 1838.51 | 1.05354 | 9.6847 | 1.93694 | 2711.72 | 9.86852 | 1838.51 | 0.367701
Parede-088 | 38.1626 (kgCO₂) | 312.239 | 1655.12 | 935.768 | 0.331023 | 1.5488 | 0.309761 | 433.665 | 1.5488 | 935.768 | 0.187154
Parede-081 | 57.2526 (kgCO₂) | 468.431 | 5353.32 | 434.04 | 1.07067 | 2.32357 | 0.464713 | 650.598 | 2.32357 | 2407.36 | 0.481472
Parede-086 | 712.515 (kgCO₂) | 5829.67 | 10934.8 | 2623.67 | 2.20696 | 28.917 | 5.7834 | 8096.76 | 28.917 | 2623.67 | 0.524734
Parede-083 | 921.005 (kgCO₂) | 7535.49 | 15050 | 2483.62 | 3.01 | 37.3784 | 7.47569 | 10466 | 37.3784 | 2483.62 | 0.496723
Parede-083 | 1007.57 (kgCO₂) | 8243.74 | 10633.8 | 3845.42 | 2.12677 | 40.8916 | 8.17831 | 11449.6 | 40.8916 | 3845.42 | 0.769085
Parede-090 | 76.5265 (kgCO₂) | 626.126 | 1200 | 2588.15 | 0.24 | 3.10578 | 0.621157 | 869.62 | 3.10578 | 2588.15 | 0.517631
Parede-090 | 589.607 (kgCO₂) | 4824.06 | 8795.88 | 2751.75 | 1.73918 | 23.9289 | 4.78577 | 6700.08 | 23.929 | 2751.75 | 0.550349
Parede-089 | 42.8716 (kgCO₂) | 350.768 | 1400 | 1242.8 | 0.28 | 1.73992 | 0.347984 | 487.178 | 1.73992 | 1242.8 | 0.24856
Parede-081 | 447.086 (kgCO₂) | 3657.98 | 12243.9 | 1481.94 | 2.44878 | 18.1447 | 3.62895 | 5080.52 | 18.1447 | 1481.94 | 0.296388
Parede-081 | 122.539 (kgCO₂) | 1002.59 | 3300.04 | 2526.74 | 0.640009 | 4.97317 | 0.994635 | 1392.49 | 4.97317 | 2526.74 | 0.505348
Parede-081 | 58.2106 (kgCO₂) | 476.269 | 1707.88 | 1469.29 | 0.321575 | 2.36244 | 0.472489 | 661.484 | 2.36247 | 1469.29 | 0.293859
Parede-084 | 67.7479 (kgCO₂) | 554.301 | 4341.1 | 600 | 0.916504 | 2.74951 | 0.549902 | 769.863 | 2.80951 | 600 | 0.12
Parede-082 | 5.41308 (kgCO₂) | 44.2888 | 648.987 | 600 | 0.0732289 | 0.219687 | 0.0439373 | 61.5122 | 0.339687 | 600 | 0.12
Parede-081 | 73.92 (kgCO₂) | 604.8 | 4800 | 600 | 1 | 3 | 0.6 | 840 | 3 | 600 | 0.12
Parede-082 | 10.3488 (kgCO₂) | 84.672 | 658.579 | 600 | 0.14 | 0.42 | 0.084 | 117.6 | 0.48 | 600 | 0.12
Parede-085 | 13.5641 (kgCO₂) | 110.979 | 1117.48 | 600 | 0.183496 | 0.550489 | 0.110098 | 154.137 | 0.550489 | 600 | 0.12
